# Generated by FakeRAM 2.0
VERSION 5.7 ;
BUSBITCHARS "[]" ;
PROPERTYDEFINITIONS
  MACRO width INTEGER ;
  MACRO depth INTEGER ;
  MACRO banks INTEGER ;
END PROPERTYDEFINITIONS
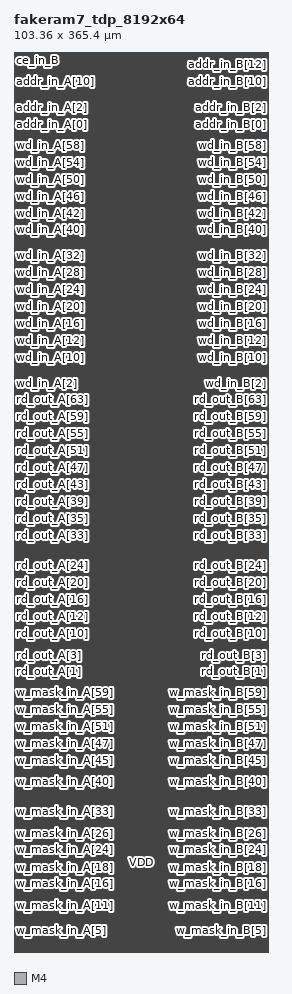
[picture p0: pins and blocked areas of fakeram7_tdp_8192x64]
MACRO fakeram7_tdp_8192x64
  PROPERTY width 64 ;
  PROPERTY depth 8192 ;
  PROPERTY banks 8 ;
  FOREIGN fakeram7_tdp_8192x64 0 0 ;
  SYMMETRY X Y ;
  SIZE 103.360 BY 365.400 ;
  CLASS BLOCK ;
  PIN w_mask_in_A[0]
    DIRECTION INPUT ;
    USE SIGNAL ;
    SHAPE ABUTMENT ;
    PORT
      LAYER M4 ;
      RECT 0.000 0.048 0.024 0.072 ;
    END
  END w_mask_in_A[0]
  PIN w_mask_in_B[0]
    DIRECTION INPUT ;
    USE SIGNAL ;
    SHAPE ABUTMENT ;
    PORT
      LAYER M4 ;
      RECT 103.336 0.048 103.360 0.072 ;
    END
  END w_mask_in_B[0]
  PIN w_mask_in_A[1]
    DIRECTION INPUT ;
    USE SIGNAL ;
    SHAPE ABUTMENT ;
    PORT
      LAYER M4 ;
      RECT 0.000 1.776 0.024 1.800 ;
    END
  END w_mask_in_A[1]
  PIN w_mask_in_B[1]
    DIRECTION INPUT ;
    USE SIGNAL ;
    SHAPE ABUTMENT ;
    PORT
      LAYER M4 ;
      RECT 103.336 1.776 103.360 1.800 ;
    END
  END w_mask_in_B[1]
  PIN w_mask_in_A[2]
    DIRECTION INPUT ;
    USE SIGNAL ;
    SHAPE ABUTMENT ;
    PORT
      LAYER M4 ;
      RECT 0.000 3.504 0.024 3.528 ;
    END
  END w_mask_in_A[2]
  PIN w_mask_in_B[2]
    DIRECTION INPUT ;
    USE SIGNAL ;
    SHAPE ABUTMENT ;
    PORT
      LAYER M4 ;
      RECT 103.336 3.504 103.360 3.528 ;
    END
  END w_mask_in_B[2]
  PIN w_mask_in_A[3]
    DIRECTION INPUT ;
    USE SIGNAL ;
    SHAPE ABUTMENT ;
    PORT
      LAYER M4 ;
      RECT 0.000 5.232 0.024 5.256 ;
    END
  END w_mask_in_A[3]
  PIN w_mask_in_B[3]
    DIRECTION INPUT ;
    USE SIGNAL ;
    SHAPE ABUTMENT ;
    PORT
      LAYER M4 ;
      RECT 103.336 5.232 103.360 5.256 ;
    END
  END w_mask_in_B[3]
  PIN w_mask_in_A[4]
    DIRECTION INPUT ;
    USE SIGNAL ;
    SHAPE ABUTMENT ;
    PORT
      LAYER M4 ;
      RECT 0.000 6.960 0.024 6.984 ;
    END
  END w_mask_in_A[4]
  PIN w_mask_in_B[4]
    DIRECTION INPUT ;
    USE SIGNAL ;
    SHAPE ABUTMENT ;
    PORT
      LAYER M4 ;
      RECT 103.336 6.960 103.360 6.984 ;
    END
  END w_mask_in_B[4]
  PIN w_mask_in_A[5]
    DIRECTION INPUT ;
    USE SIGNAL ;
    SHAPE ABUTMENT ;
    PORT
      LAYER M4 ;
      RECT 0.000 8.688 0.024 8.712 ;
    END
  END w_mask_in_A[5]
  PIN w_mask_in_B[5]
    DIRECTION INPUT ;
    USE SIGNAL ;
    SHAPE ABUTMENT ;
    PORT
      LAYER M4 ;
      RECT 103.336 8.688 103.360 8.712 ;
    END
  END w_mask_in_B[5]
  PIN w_mask_in_A[6]
    DIRECTION INPUT ;
    USE SIGNAL ;
    SHAPE ABUTMENT ;
    PORT
      LAYER M4 ;
      RECT 0.000 10.416 0.024 10.440 ;
    END
  END w_mask_in_A[6]
  PIN w_mask_in_B[6]
    DIRECTION INPUT ;
    USE SIGNAL ;
    SHAPE ABUTMENT ;
    PORT
      LAYER M4 ;
      RECT 103.336 10.416 103.360 10.440 ;
    END
  END w_mask_in_B[6]
  PIN w_mask_in_A[7]
    DIRECTION INPUT ;
    USE SIGNAL ;
    SHAPE ABUTMENT ;
    PORT
      LAYER M4 ;
      RECT 0.000 12.144 0.024 12.168 ;
    END
  END w_mask_in_A[7]
  PIN w_mask_in_B[7]
    DIRECTION INPUT ;
    USE SIGNAL ;
    SHAPE ABUTMENT ;
    PORT
      LAYER M4 ;
      RECT 103.336 12.144 103.360 12.168 ;
    END
  END w_mask_in_B[7]
  PIN w_mask_in_A[8]
    DIRECTION INPUT ;
    USE SIGNAL ;
    SHAPE ABUTMENT ;
    PORT
      LAYER M4 ;
      RECT 0.000 13.872 0.024 13.896 ;
    END
  END w_mask_in_A[8]
  PIN w_mask_in_B[8]
    DIRECTION INPUT ;
    USE SIGNAL ;
    SHAPE ABUTMENT ;
    PORT
      LAYER M4 ;
      RECT 103.336 13.872 103.360 13.896 ;
    END
  END w_mask_in_B[8]
  PIN w_mask_in_A[9]
    DIRECTION INPUT ;
    USE SIGNAL ;
    SHAPE ABUTMENT ;
    PORT
      LAYER M4 ;
      RECT 0.000 15.600 0.024 15.624 ;
    END
  END w_mask_in_A[9]
  PIN w_mask_in_B[9]
    DIRECTION INPUT ;
    USE SIGNAL ;
    SHAPE ABUTMENT ;
    PORT
      LAYER M4 ;
      RECT 103.336 15.600 103.360 15.624 ;
    END
  END w_mask_in_B[9]
  PIN w_mask_in_A[10]
    DIRECTION INPUT ;
    USE SIGNAL ;
    SHAPE ABUTMENT ;
    PORT
      LAYER M4 ;
      RECT 0.000 17.328 0.024 17.352 ;
    END
  END w_mask_in_A[10]
  PIN w_mask_in_B[10]
    DIRECTION INPUT ;
    USE SIGNAL ;
    SHAPE ABUTMENT ;
    PORT
      LAYER M4 ;
      RECT 103.336 17.328 103.360 17.352 ;
    END
  END w_mask_in_B[10]
  PIN w_mask_in_A[11]
    DIRECTION INPUT ;
    USE SIGNAL ;
    SHAPE ABUTMENT ;
    PORT
      LAYER M4 ;
      RECT 0.000 19.056 0.024 19.080 ;
    END
  END w_mask_in_A[11]
  PIN w_mask_in_B[11]
    DIRECTION INPUT ;
    USE SIGNAL ;
    SHAPE ABUTMENT ;
    PORT
      LAYER M4 ;
      RECT 103.336 19.056 103.360 19.080 ;
    END
  END w_mask_in_B[11]
  PIN w_mask_in_A[12]
    DIRECTION INPUT ;
    USE SIGNAL ;
    SHAPE ABUTMENT ;
    PORT
      LAYER M4 ;
      RECT 0.000 20.784 0.024 20.808 ;
    END
  END w_mask_in_A[12]
  PIN w_mask_in_B[12]
    DIRECTION INPUT ;
    USE SIGNAL ;
    SHAPE ABUTMENT ;
    PORT
      LAYER M4 ;
      RECT 103.336 20.784 103.360 20.808 ;
    END
  END w_mask_in_B[12]
  PIN w_mask_in_A[13]
    DIRECTION INPUT ;
    USE SIGNAL ;
    SHAPE ABUTMENT ;
    PORT
      LAYER M4 ;
      RECT 0.000 22.512 0.024 22.536 ;
    END
  END w_mask_in_A[13]
  PIN w_mask_in_B[13]
    DIRECTION INPUT ;
    USE SIGNAL ;
    SHAPE ABUTMENT ;
    PORT
      LAYER M4 ;
      RECT 103.336 22.512 103.360 22.536 ;
    END
  END w_mask_in_B[13]
  PIN w_mask_in_A[14]
    DIRECTION INPUT ;
    USE SIGNAL ;
    SHAPE ABUTMENT ;
    PORT
      LAYER M4 ;
      RECT 0.000 24.240 0.024 24.264 ;
    END
  END w_mask_in_A[14]
  PIN w_mask_in_B[14]
    DIRECTION INPUT ;
    USE SIGNAL ;
    SHAPE ABUTMENT ;
    PORT
      LAYER M4 ;
      RECT 103.336 24.240 103.360 24.264 ;
    END
  END w_mask_in_B[14]
  PIN w_mask_in_A[15]
    DIRECTION INPUT ;
    USE SIGNAL ;
    SHAPE ABUTMENT ;
    PORT
      LAYER M4 ;
      RECT 0.000 25.968 0.024 25.992 ;
    END
  END w_mask_in_A[15]
  PIN w_mask_in_B[15]
    DIRECTION INPUT ;
    USE SIGNAL ;
    SHAPE ABUTMENT ;
    PORT
      LAYER M4 ;
      RECT 103.336 25.968 103.360 25.992 ;
    END
  END w_mask_in_B[15]
  PIN w_mask_in_A[16]
    DIRECTION INPUT ;
    USE SIGNAL ;
    SHAPE ABUTMENT ;
    PORT
      LAYER M4 ;
      RECT 0.000 27.696 0.024 27.720 ;
    END
  END w_mask_in_A[16]
  PIN w_mask_in_B[16]
    DIRECTION INPUT ;
    USE SIGNAL ;
    SHAPE ABUTMENT ;
    PORT
      LAYER M4 ;
      RECT 103.336 27.696 103.360 27.720 ;
    END
  END w_mask_in_B[16]
  PIN w_mask_in_A[17]
    DIRECTION INPUT ;
    USE SIGNAL ;
    SHAPE ABUTMENT ;
    PORT
      LAYER M4 ;
      RECT 0.000 29.424 0.024 29.448 ;
    END
  END w_mask_in_A[17]
  PIN w_mask_in_B[17]
    DIRECTION INPUT ;
    USE SIGNAL ;
    SHAPE ABUTMENT ;
    PORT
      LAYER M4 ;
      RECT 103.336 29.424 103.360 29.448 ;
    END
  END w_mask_in_B[17]
  PIN w_mask_in_A[18]
    DIRECTION INPUT ;
    USE SIGNAL ;
    SHAPE ABUTMENT ;
    PORT
      LAYER M4 ;
      RECT 0.000 31.152 0.024 31.176 ;
    END
  END w_mask_in_A[18]
  PIN w_mask_in_B[18]
    DIRECTION INPUT ;
    USE SIGNAL ;
    SHAPE ABUTMENT ;
    PORT
      LAYER M4 ;
      RECT 103.336 31.152 103.360 31.176 ;
    END
  END w_mask_in_B[18]
  PIN w_mask_in_A[19]
    DIRECTION INPUT ;
    USE SIGNAL ;
    SHAPE ABUTMENT ;
    PORT
      LAYER M4 ;
      RECT 0.000 32.880 0.024 32.904 ;
    END
  END w_mask_in_A[19]
  PIN w_mask_in_B[19]
    DIRECTION INPUT ;
    USE SIGNAL ;
    SHAPE ABUTMENT ;
    PORT
      LAYER M4 ;
      RECT 103.336 32.880 103.360 32.904 ;
    END
  END w_mask_in_B[19]
  PIN w_mask_in_A[20]
    DIRECTION INPUT ;
    USE SIGNAL ;
    SHAPE ABUTMENT ;
    PORT
      LAYER M4 ;
      RECT 0.000 34.608 0.024 34.632 ;
    END
  END w_mask_in_A[20]
  PIN w_mask_in_B[20]
    DIRECTION INPUT ;
    USE SIGNAL ;
    SHAPE ABUTMENT ;
    PORT
      LAYER M4 ;
      RECT 103.336 34.608 103.360 34.632 ;
    END
  END w_mask_in_B[20]
  PIN w_mask_in_A[21]
    DIRECTION INPUT ;
    USE SIGNAL ;
    SHAPE ABUTMENT ;
    PORT
      LAYER M4 ;
      RECT 0.000 36.336 0.024 36.360 ;
    END
  END w_mask_in_A[21]
  PIN w_mask_in_B[21]
    DIRECTION INPUT ;
    USE SIGNAL ;
    SHAPE ABUTMENT ;
    PORT
      LAYER M4 ;
      RECT 103.336 36.336 103.360 36.360 ;
    END
  END w_mask_in_B[21]
  PIN w_mask_in_A[22]
    DIRECTION INPUT ;
    USE SIGNAL ;
    SHAPE ABUTMENT ;
    PORT
      LAYER M4 ;
      RECT 0.000 38.064 0.024 38.088 ;
    END
  END w_mask_in_A[22]
  PIN w_mask_in_B[22]
    DIRECTION INPUT ;
    USE SIGNAL ;
    SHAPE ABUTMENT ;
    PORT
      LAYER M4 ;
      RECT 103.336 38.064 103.360 38.088 ;
    END
  END w_mask_in_B[22]
  PIN w_mask_in_A[23]
    DIRECTION INPUT ;
    USE SIGNAL ;
    SHAPE ABUTMENT ;
    PORT
      LAYER M4 ;
      RECT 0.000 39.792 0.024 39.816 ;
    END
  END w_mask_in_A[23]
  PIN w_mask_in_B[23]
    DIRECTION INPUT ;
    USE SIGNAL ;
    SHAPE ABUTMENT ;
    PORT
      LAYER M4 ;
      RECT 103.336 39.792 103.360 39.816 ;
    END
  END w_mask_in_B[23]
  PIN w_mask_in_A[24]
    DIRECTION INPUT ;
    USE SIGNAL ;
    SHAPE ABUTMENT ;
    PORT
      LAYER M4 ;
      RECT 0.000 41.520 0.024 41.544 ;
    END
  END w_mask_in_A[24]
  PIN w_mask_in_B[24]
    DIRECTION INPUT ;
    USE SIGNAL ;
    SHAPE ABUTMENT ;
    PORT
      LAYER M4 ;
      RECT 103.336 41.520 103.360 41.544 ;
    END
  END w_mask_in_B[24]
  PIN w_mask_in_A[25]
    DIRECTION INPUT ;
    USE SIGNAL ;
    SHAPE ABUTMENT ;
    PORT
      LAYER M4 ;
      RECT 0.000 43.248 0.024 43.272 ;
    END
  END w_mask_in_A[25]
  PIN w_mask_in_B[25]
    DIRECTION INPUT ;
    USE SIGNAL ;
    SHAPE ABUTMENT ;
    PORT
      LAYER M4 ;
      RECT 103.336 43.248 103.360 43.272 ;
    END
  END w_mask_in_B[25]
  PIN w_mask_in_A[26]
    DIRECTION INPUT ;
    USE SIGNAL ;
    SHAPE ABUTMENT ;
    PORT
      LAYER M4 ;
      RECT 0.000 44.976 0.024 45.000 ;
    END
  END w_mask_in_A[26]
  PIN w_mask_in_B[26]
    DIRECTION INPUT ;
    USE SIGNAL ;
    SHAPE ABUTMENT ;
    PORT
      LAYER M4 ;
      RECT 103.336 44.976 103.360 45.000 ;
    END
  END w_mask_in_B[26]
  PIN w_mask_in_A[27]
    DIRECTION INPUT ;
    USE SIGNAL ;
    SHAPE ABUTMENT ;
    PORT
      LAYER M4 ;
      RECT 0.000 46.704 0.024 46.728 ;
    END
  END w_mask_in_A[27]
  PIN w_mask_in_B[27]
    DIRECTION INPUT ;
    USE SIGNAL ;
    SHAPE ABUTMENT ;
    PORT
      LAYER M4 ;
      RECT 103.336 46.704 103.360 46.728 ;
    END
  END w_mask_in_B[27]
  PIN w_mask_in_A[28]
    DIRECTION INPUT ;
    USE SIGNAL ;
    SHAPE ABUTMENT ;
    PORT
      LAYER M4 ;
      RECT 0.000 48.432 0.024 48.456 ;
    END
  END w_mask_in_A[28]
  PIN w_mask_in_B[28]
    DIRECTION INPUT ;
    USE SIGNAL ;
    SHAPE ABUTMENT ;
    PORT
      LAYER M4 ;
      RECT 103.336 48.432 103.360 48.456 ;
    END
  END w_mask_in_B[28]
  PIN w_mask_in_A[29]
    DIRECTION INPUT ;
    USE SIGNAL ;
    SHAPE ABUTMENT ;
    PORT
      LAYER M4 ;
      RECT 0.000 50.160 0.024 50.184 ;
    END
  END w_mask_in_A[29]
  PIN w_mask_in_B[29]
    DIRECTION INPUT ;
    USE SIGNAL ;
    SHAPE ABUTMENT ;
    PORT
      LAYER M4 ;
      RECT 103.336 50.160 103.360 50.184 ;
    END
  END w_mask_in_B[29]
  PIN w_mask_in_A[30]
    DIRECTION INPUT ;
    USE SIGNAL ;
    SHAPE ABUTMENT ;
    PORT
      LAYER M4 ;
      RECT 0.000 51.888 0.024 51.912 ;
    END
  END w_mask_in_A[30]
  PIN w_mask_in_B[30]
    DIRECTION INPUT ;
    USE SIGNAL ;
    SHAPE ABUTMENT ;
    PORT
      LAYER M4 ;
      RECT 103.336 51.888 103.360 51.912 ;
    END
  END w_mask_in_B[30]
  PIN w_mask_in_A[31]
    DIRECTION INPUT ;
    USE SIGNAL ;
    SHAPE ABUTMENT ;
    PORT
      LAYER M4 ;
      RECT 0.000 53.616 0.024 53.640 ;
    END
  END w_mask_in_A[31]
  PIN w_mask_in_B[31]
    DIRECTION INPUT ;
    USE SIGNAL ;
    SHAPE ABUTMENT ;
    PORT
      LAYER M4 ;
      RECT 103.336 53.616 103.360 53.640 ;
    END
  END w_mask_in_B[31]
  PIN w_mask_in_A[32]
    DIRECTION INPUT ;
    USE SIGNAL ;
    SHAPE ABUTMENT ;
    PORT
      LAYER M4 ;
      RECT 0.000 55.344 0.024 55.368 ;
    END
  END w_mask_in_A[32]
  PIN w_mask_in_B[32]
    DIRECTION INPUT ;
    USE SIGNAL ;
    SHAPE ABUTMENT ;
    PORT
      LAYER M4 ;
      RECT 103.336 55.344 103.360 55.368 ;
    END
  END w_mask_in_B[32]
  PIN w_mask_in_A[33]
    DIRECTION INPUT ;
    USE SIGNAL ;
    SHAPE ABUTMENT ;
    PORT
      LAYER M4 ;
      RECT 0.000 57.072 0.024 57.096 ;
    END
  END w_mask_in_A[33]
  PIN w_mask_in_B[33]
    DIRECTION INPUT ;
    USE SIGNAL ;
    SHAPE ABUTMENT ;
    PORT
      LAYER M4 ;
      RECT 103.336 57.072 103.360 57.096 ;
    END
  END w_mask_in_B[33]
  PIN w_mask_in_A[34]
    DIRECTION INPUT ;
    USE SIGNAL ;
    SHAPE ABUTMENT ;
    PORT
      LAYER M4 ;
      RECT 0.000 58.800 0.024 58.824 ;
    END
  END w_mask_in_A[34]
  PIN w_mask_in_B[34]
    DIRECTION INPUT ;
    USE SIGNAL ;
    SHAPE ABUTMENT ;
    PORT
      LAYER M4 ;
      RECT 103.336 58.800 103.360 58.824 ;
    END
  END w_mask_in_B[34]
  PIN w_mask_in_A[35]
    DIRECTION INPUT ;
    USE SIGNAL ;
    SHAPE ABUTMENT ;
    PORT
      LAYER M4 ;
      RECT 0.000 60.528 0.024 60.552 ;
    END
  END w_mask_in_A[35]
  PIN w_mask_in_B[35]
    DIRECTION INPUT ;
    USE SIGNAL ;
    SHAPE ABUTMENT ;
    PORT
      LAYER M4 ;
      RECT 103.336 60.528 103.360 60.552 ;
    END
  END w_mask_in_B[35]
  PIN w_mask_in_A[36]
    DIRECTION INPUT ;
    USE SIGNAL ;
    SHAPE ABUTMENT ;
    PORT
      LAYER M4 ;
      RECT 0.000 62.256 0.024 62.280 ;
    END
  END w_mask_in_A[36]
  PIN w_mask_in_B[36]
    DIRECTION INPUT ;
    USE SIGNAL ;
    SHAPE ABUTMENT ;
    PORT
      LAYER M4 ;
      RECT 103.336 62.256 103.360 62.280 ;
    END
  END w_mask_in_B[36]
  PIN w_mask_in_A[37]
    DIRECTION INPUT ;
    USE SIGNAL ;
    SHAPE ABUTMENT ;
    PORT
      LAYER M4 ;
      RECT 0.000 63.984 0.024 64.008 ;
    END
  END w_mask_in_A[37]
  PIN w_mask_in_B[37]
    DIRECTION INPUT ;
    USE SIGNAL ;
    SHAPE ABUTMENT ;
    PORT
      LAYER M4 ;
      RECT 103.336 63.984 103.360 64.008 ;
    END
  END w_mask_in_B[37]
  PIN w_mask_in_A[38]
    DIRECTION INPUT ;
    USE SIGNAL ;
    SHAPE ABUTMENT ;
    PORT
      LAYER M4 ;
      RECT 0.000 65.712 0.024 65.736 ;
    END
  END w_mask_in_A[38]
  PIN w_mask_in_B[38]
    DIRECTION INPUT ;
    USE SIGNAL ;
    SHAPE ABUTMENT ;
    PORT
      LAYER M4 ;
      RECT 103.336 65.712 103.360 65.736 ;
    END
  END w_mask_in_B[38]
  PIN w_mask_in_A[39]
    DIRECTION INPUT ;
    USE SIGNAL ;
    SHAPE ABUTMENT ;
    PORT
      LAYER M4 ;
      RECT 0.000 67.440 0.024 67.464 ;
    END
  END w_mask_in_A[39]
  PIN w_mask_in_B[39]
    DIRECTION INPUT ;
    USE SIGNAL ;
    SHAPE ABUTMENT ;
    PORT
      LAYER M4 ;
      RECT 103.336 67.440 103.360 67.464 ;
    END
  END w_mask_in_B[39]
  PIN w_mask_in_A[40]
    DIRECTION INPUT ;
    USE SIGNAL ;
    SHAPE ABUTMENT ;
    PORT
      LAYER M4 ;
      RECT 0.000 69.168 0.024 69.192 ;
    END
  END w_mask_in_A[40]
  PIN w_mask_in_B[40]
    DIRECTION INPUT ;
    USE SIGNAL ;
    SHAPE ABUTMENT ;
    PORT
      LAYER M4 ;
      RECT 103.336 69.168 103.360 69.192 ;
    END
  END w_mask_in_B[40]
  PIN w_mask_in_A[41]
    DIRECTION INPUT ;
    USE SIGNAL ;
    SHAPE ABUTMENT ;
    PORT
      LAYER M4 ;
      RECT 0.000 70.896 0.024 70.920 ;
    END
  END w_mask_in_A[41]
  PIN w_mask_in_B[41]
    DIRECTION INPUT ;
    USE SIGNAL ;
    SHAPE ABUTMENT ;
    PORT
      LAYER M4 ;
      RECT 103.336 70.896 103.360 70.920 ;
    END
  END w_mask_in_B[41]
  PIN w_mask_in_A[42]
    DIRECTION INPUT ;
    USE SIGNAL ;
    SHAPE ABUTMENT ;
    PORT
      LAYER M4 ;
      RECT 0.000 72.624 0.024 72.648 ;
    END
  END w_mask_in_A[42]
  PIN w_mask_in_B[42]
    DIRECTION INPUT ;
    USE SIGNAL ;
    SHAPE ABUTMENT ;
    PORT
      LAYER M4 ;
      RECT 103.336 72.624 103.360 72.648 ;
    END
  END w_mask_in_B[42]
  PIN w_mask_in_A[43]
    DIRECTION INPUT ;
    USE SIGNAL ;
    SHAPE ABUTMENT ;
    PORT
      LAYER M4 ;
      RECT 0.000 74.352 0.024 74.376 ;
    END
  END w_mask_in_A[43]
  PIN w_mask_in_B[43]
    DIRECTION INPUT ;
    USE SIGNAL ;
    SHAPE ABUTMENT ;
    PORT
      LAYER M4 ;
      RECT 103.336 74.352 103.360 74.376 ;
    END
  END w_mask_in_B[43]
  PIN w_mask_in_A[44]
    DIRECTION INPUT ;
    USE SIGNAL ;
    SHAPE ABUTMENT ;
    PORT
      LAYER M4 ;
      RECT 0.000 76.080 0.024 76.104 ;
    END
  END w_mask_in_A[44]
  PIN w_mask_in_B[44]
    DIRECTION INPUT ;
    USE SIGNAL ;
    SHAPE ABUTMENT ;
    PORT
      LAYER M4 ;
      RECT 103.336 76.080 103.360 76.104 ;
    END
  END w_mask_in_B[44]
  PIN w_mask_in_A[45]
    DIRECTION INPUT ;
    USE SIGNAL ;
    SHAPE ABUTMENT ;
    PORT
      LAYER M4 ;
      RECT 0.000 77.808 0.024 77.832 ;
    END
  END w_mask_in_A[45]
  PIN w_mask_in_B[45]
    DIRECTION INPUT ;
    USE SIGNAL ;
    SHAPE ABUTMENT ;
    PORT
      LAYER M4 ;
      RECT 103.336 77.808 103.360 77.832 ;
    END
  END w_mask_in_B[45]
  PIN w_mask_in_A[46]
    DIRECTION INPUT ;
    USE SIGNAL ;
    SHAPE ABUTMENT ;
    PORT
      LAYER M4 ;
      RECT 0.000 79.536 0.024 79.560 ;
    END
  END w_mask_in_A[46]
  PIN w_mask_in_B[46]
    DIRECTION INPUT ;
    USE SIGNAL ;
    SHAPE ABUTMENT ;
    PORT
      LAYER M4 ;
      RECT 103.336 79.536 103.360 79.560 ;
    END
  END w_mask_in_B[46]
  PIN w_mask_in_A[47]
    DIRECTION INPUT ;
    USE SIGNAL ;
    SHAPE ABUTMENT ;
    PORT
      LAYER M4 ;
      RECT 0.000 81.264 0.024 81.288 ;
    END
  END w_mask_in_A[47]
  PIN w_mask_in_B[47]
    DIRECTION INPUT ;
    USE SIGNAL ;
    SHAPE ABUTMENT ;
    PORT
      LAYER M4 ;
      RECT 103.336 81.264 103.360 81.288 ;
    END
  END w_mask_in_B[47]
  PIN w_mask_in_A[48]
    DIRECTION INPUT ;
    USE SIGNAL ;
    SHAPE ABUTMENT ;
    PORT
      LAYER M4 ;
      RECT 0.000 82.992 0.024 83.016 ;
    END
  END w_mask_in_A[48]
  PIN w_mask_in_B[48]
    DIRECTION INPUT ;
    USE SIGNAL ;
    SHAPE ABUTMENT ;
    PORT
      LAYER M4 ;
      RECT 103.336 82.992 103.360 83.016 ;
    END
  END w_mask_in_B[48]
  PIN w_mask_in_A[49]
    DIRECTION INPUT ;
    USE SIGNAL ;
    SHAPE ABUTMENT ;
    PORT
      LAYER M4 ;
      RECT 0.000 84.720 0.024 84.744 ;
    END
  END w_mask_in_A[49]
  PIN w_mask_in_B[49]
    DIRECTION INPUT ;
    USE SIGNAL ;
    SHAPE ABUTMENT ;
    PORT
      LAYER M4 ;
      RECT 103.336 84.720 103.360 84.744 ;
    END
  END w_mask_in_B[49]
  PIN w_mask_in_A[50]
    DIRECTION INPUT ;
    USE SIGNAL ;
    SHAPE ABUTMENT ;
    PORT
      LAYER M4 ;
      RECT 0.000 86.448 0.024 86.472 ;
    END
  END w_mask_in_A[50]
  PIN w_mask_in_B[50]
    DIRECTION INPUT ;
    USE SIGNAL ;
    SHAPE ABUTMENT ;
    PORT
      LAYER M4 ;
      RECT 103.336 86.448 103.360 86.472 ;
    END
  END w_mask_in_B[50]
  PIN w_mask_in_A[51]
    DIRECTION INPUT ;
    USE SIGNAL ;
    SHAPE ABUTMENT ;
    PORT
      LAYER M4 ;
      RECT 0.000 88.176 0.024 88.200 ;
    END
  END w_mask_in_A[51]
  PIN w_mask_in_B[51]
    DIRECTION INPUT ;
    USE SIGNAL ;
    SHAPE ABUTMENT ;
    PORT
      LAYER M4 ;
      RECT 103.336 88.176 103.360 88.200 ;
    END
  END w_mask_in_B[51]
  PIN w_mask_in_A[52]
    DIRECTION INPUT ;
    USE SIGNAL ;
    SHAPE ABUTMENT ;
    PORT
      LAYER M4 ;
      RECT 0.000 89.904 0.024 89.928 ;
    END
  END w_mask_in_A[52]
  PIN w_mask_in_B[52]
    DIRECTION INPUT ;
    USE SIGNAL ;
    SHAPE ABUTMENT ;
    PORT
      LAYER M4 ;
      RECT 103.336 89.904 103.360 89.928 ;
    END
  END w_mask_in_B[52]
  PIN w_mask_in_A[53]
    DIRECTION INPUT ;
    USE SIGNAL ;
    SHAPE ABUTMENT ;
    PORT
      LAYER M4 ;
      RECT 0.000 91.632 0.024 91.656 ;
    END
  END w_mask_in_A[53]
  PIN w_mask_in_B[53]
    DIRECTION INPUT ;
    USE SIGNAL ;
    SHAPE ABUTMENT ;
    PORT
      LAYER M4 ;
      RECT 103.336 91.632 103.360 91.656 ;
    END
  END w_mask_in_B[53]
  PIN w_mask_in_A[54]
    DIRECTION INPUT ;
    USE SIGNAL ;
    SHAPE ABUTMENT ;
    PORT
      LAYER M4 ;
      RECT 0.000 93.360 0.024 93.384 ;
    END
  END w_mask_in_A[54]
  PIN w_mask_in_B[54]
    DIRECTION INPUT ;
    USE SIGNAL ;
    SHAPE ABUTMENT ;
    PORT
      LAYER M4 ;
      RECT 103.336 93.360 103.360 93.384 ;
    END
  END w_mask_in_B[54]
  PIN w_mask_in_A[55]
    DIRECTION INPUT ;
    USE SIGNAL ;
    SHAPE ABUTMENT ;
    PORT
      LAYER M4 ;
      RECT 0.000 95.088 0.024 95.112 ;
    END
  END w_mask_in_A[55]
  PIN w_mask_in_B[55]
    DIRECTION INPUT ;
    USE SIGNAL ;
    SHAPE ABUTMENT ;
    PORT
      LAYER M4 ;
      RECT 103.336 95.088 103.360 95.112 ;
    END
  END w_mask_in_B[55]
  PIN w_mask_in_A[56]
    DIRECTION INPUT ;
    USE SIGNAL ;
    SHAPE ABUTMENT ;
    PORT
      LAYER M4 ;
      RECT 0.000 96.816 0.024 96.840 ;
    END
  END w_mask_in_A[56]
  PIN w_mask_in_B[56]
    DIRECTION INPUT ;
    USE SIGNAL ;
    SHAPE ABUTMENT ;
    PORT
      LAYER M4 ;
      RECT 103.336 96.816 103.360 96.840 ;
    END
  END w_mask_in_B[56]
  PIN w_mask_in_A[57]
    DIRECTION INPUT ;
    USE SIGNAL ;
    SHAPE ABUTMENT ;
    PORT
      LAYER M4 ;
      RECT 0.000 98.544 0.024 98.568 ;
    END
  END w_mask_in_A[57]
  PIN w_mask_in_B[57]
    DIRECTION INPUT ;
    USE SIGNAL ;
    SHAPE ABUTMENT ;
    PORT
      LAYER M4 ;
      RECT 103.336 98.544 103.360 98.568 ;
    END
  END w_mask_in_B[57]
  PIN w_mask_in_A[58]
    DIRECTION INPUT ;
    USE SIGNAL ;
    SHAPE ABUTMENT ;
    PORT
      LAYER M4 ;
      RECT 0.000 100.272 0.024 100.296 ;
    END
  END w_mask_in_A[58]
  PIN w_mask_in_B[58]
    DIRECTION INPUT ;
    USE SIGNAL ;
    SHAPE ABUTMENT ;
    PORT
      LAYER M4 ;
      RECT 103.336 100.272 103.360 100.296 ;
    END
  END w_mask_in_B[58]
  PIN w_mask_in_A[59]
    DIRECTION INPUT ;
    USE SIGNAL ;
    SHAPE ABUTMENT ;
    PORT
      LAYER M4 ;
      RECT 0.000 102.000 0.024 102.024 ;
    END
  END w_mask_in_A[59]
  PIN w_mask_in_B[59]
    DIRECTION INPUT ;
    USE SIGNAL ;
    SHAPE ABUTMENT ;
    PORT
      LAYER M4 ;
      RECT 103.336 102.000 103.360 102.024 ;
    END
  END w_mask_in_B[59]
  PIN w_mask_in_A[60]
    DIRECTION INPUT ;
    USE SIGNAL ;
    SHAPE ABUTMENT ;
    PORT
      LAYER M4 ;
      RECT 0.000 103.728 0.024 103.752 ;
    END
  END w_mask_in_A[60]
  PIN w_mask_in_B[60]
    DIRECTION INPUT ;
    USE SIGNAL ;
    SHAPE ABUTMENT ;
    PORT
      LAYER M4 ;
      RECT 103.336 103.728 103.360 103.752 ;
    END
  END w_mask_in_B[60]
  PIN w_mask_in_A[61]
    DIRECTION INPUT ;
    USE SIGNAL ;
    SHAPE ABUTMENT ;
    PORT
      LAYER M4 ;
      RECT 0.000 105.456 0.024 105.480 ;
    END
  END w_mask_in_A[61]
  PIN w_mask_in_B[61]
    DIRECTION INPUT ;
    USE SIGNAL ;
    SHAPE ABUTMENT ;
    PORT
      LAYER M4 ;
      RECT 103.336 105.456 103.360 105.480 ;
    END
  END w_mask_in_B[61]
  PIN w_mask_in_A[62]
    DIRECTION INPUT ;
    USE SIGNAL ;
    SHAPE ABUTMENT ;
    PORT
      LAYER M4 ;
      RECT 0.000 107.184 0.024 107.208 ;
    END
  END w_mask_in_A[62]
  PIN w_mask_in_B[62]
    DIRECTION INPUT ;
    USE SIGNAL ;
    SHAPE ABUTMENT ;
    PORT
      LAYER M4 ;
      RECT 103.336 107.184 103.360 107.208 ;
    END
  END w_mask_in_B[62]
  PIN w_mask_in_A[63]
    DIRECTION INPUT ;
    USE SIGNAL ;
    SHAPE ABUTMENT ;
    PORT
      LAYER M4 ;
      RECT 0.000 108.912 0.024 108.936 ;
    END
  END w_mask_in_A[63]
  PIN w_mask_in_B[63]
    DIRECTION INPUT ;
    USE SIGNAL ;
    SHAPE ABUTMENT ;
    PORT
      LAYER M4 ;
      RECT 103.336 108.912 103.360 108.936 ;
    END
  END w_mask_in_B[63]
  PIN rd_out_A[0]
    DIRECTION OUTPUT ;
    USE SIGNAL ;
    SHAPE ABUTMENT ;
    PORT
      LAYER M4 ;
      RECT 0.000 112.080 0.024 112.104 ;
    END
  END rd_out_A[0]
  PIN rd_out_B[0]
    DIRECTION OUTPUT ;
    USE SIGNAL ;
    SHAPE ABUTMENT ;
    PORT
      LAYER M4 ;
      RECT 103.336 112.080 103.360 112.104 ;
    END
  END rd_out_B[0]
  PIN rd_out_A[1]
    DIRECTION OUTPUT ;
    USE SIGNAL ;
    SHAPE ABUTMENT ;
    PORT
      LAYER M4 ;
      RECT 0.000 113.808 0.024 113.832 ;
    END
  END rd_out_A[1]
  PIN rd_out_B[1]
    DIRECTION OUTPUT ;
    USE SIGNAL ;
    SHAPE ABUTMENT ;
    PORT
      LAYER M4 ;
      RECT 103.336 113.808 103.360 113.832 ;
    END
  END rd_out_B[1]
  PIN rd_out_A[2]
    DIRECTION OUTPUT ;
    USE SIGNAL ;
    SHAPE ABUTMENT ;
    PORT
      LAYER M4 ;
      RECT 0.000 115.536 0.024 115.560 ;
    END
  END rd_out_A[2]
  PIN rd_out_B[2]
    DIRECTION OUTPUT ;
    USE SIGNAL ;
    SHAPE ABUTMENT ;
    PORT
      LAYER M4 ;
      RECT 103.336 115.536 103.360 115.560 ;
    END
  END rd_out_B[2]
  PIN rd_out_A[3]
    DIRECTION OUTPUT ;
    USE SIGNAL ;
    SHAPE ABUTMENT ;
    PORT
      LAYER M4 ;
      RECT 0.000 117.264 0.024 117.288 ;
    END
  END rd_out_A[3]
  PIN rd_out_B[3]
    DIRECTION OUTPUT ;
    USE SIGNAL ;
    SHAPE ABUTMENT ;
    PORT
      LAYER M4 ;
      RECT 103.336 117.264 103.360 117.288 ;
    END
  END rd_out_B[3]
  PIN rd_out_A[4]
    DIRECTION OUTPUT ;
    USE SIGNAL ;
    SHAPE ABUTMENT ;
    PORT
      LAYER M4 ;
      RECT 0.000 118.992 0.024 119.016 ;
    END
  END rd_out_A[4]
  PIN rd_out_B[4]
    DIRECTION OUTPUT ;
    USE SIGNAL ;
    SHAPE ABUTMENT ;
    PORT
      LAYER M4 ;
      RECT 103.336 118.992 103.360 119.016 ;
    END
  END rd_out_B[4]
  PIN rd_out_A[5]
    DIRECTION OUTPUT ;
    USE SIGNAL ;
    SHAPE ABUTMENT ;
    PORT
      LAYER M4 ;
      RECT 0.000 120.720 0.024 120.744 ;
    END
  END rd_out_A[5]
  PIN rd_out_B[5]
    DIRECTION OUTPUT ;
    USE SIGNAL ;
    SHAPE ABUTMENT ;
    PORT
      LAYER M4 ;
      RECT 103.336 120.720 103.360 120.744 ;
    END
  END rd_out_B[5]
  PIN rd_out_A[6]
    DIRECTION OUTPUT ;
    USE SIGNAL ;
    SHAPE ABUTMENT ;
    PORT
      LAYER M4 ;
      RECT 0.000 122.448 0.024 122.472 ;
    END
  END rd_out_A[6]
  PIN rd_out_B[6]
    DIRECTION OUTPUT ;
    USE SIGNAL ;
    SHAPE ABUTMENT ;
    PORT
      LAYER M4 ;
      RECT 103.336 122.448 103.360 122.472 ;
    END
  END rd_out_B[6]
  PIN rd_out_A[7]
    DIRECTION OUTPUT ;
    USE SIGNAL ;
    SHAPE ABUTMENT ;
    PORT
      LAYER M4 ;
      RECT 0.000 124.176 0.024 124.200 ;
    END
  END rd_out_A[7]
  PIN rd_out_B[7]
    DIRECTION OUTPUT ;
    USE SIGNAL ;
    SHAPE ABUTMENT ;
    PORT
      LAYER M4 ;
      RECT 103.336 124.176 103.360 124.200 ;
    END
  END rd_out_B[7]
  PIN rd_out_A[8]
    DIRECTION OUTPUT ;
    USE SIGNAL ;
    SHAPE ABUTMENT ;
    PORT
      LAYER M4 ;
      RECT 0.000 125.904 0.024 125.928 ;
    END
  END rd_out_A[8]
  PIN rd_out_B[8]
    DIRECTION OUTPUT ;
    USE SIGNAL ;
    SHAPE ABUTMENT ;
    PORT
      LAYER M4 ;
      RECT 103.336 125.904 103.360 125.928 ;
    END
  END rd_out_B[8]
  PIN rd_out_A[9]
    DIRECTION OUTPUT ;
    USE SIGNAL ;
    SHAPE ABUTMENT ;
    PORT
      LAYER M4 ;
      RECT 0.000 127.632 0.024 127.656 ;
    END
  END rd_out_A[9]
  PIN rd_out_B[9]
    DIRECTION OUTPUT ;
    USE SIGNAL ;
    SHAPE ABUTMENT ;
    PORT
      LAYER M4 ;
      RECT 103.336 127.632 103.360 127.656 ;
    END
  END rd_out_B[9]
  PIN rd_out_A[10]
    DIRECTION OUTPUT ;
    USE SIGNAL ;
    SHAPE ABUTMENT ;
    PORT
      LAYER M4 ;
      RECT 0.000 129.360 0.024 129.384 ;
    END
  END rd_out_A[10]
  PIN rd_out_B[10]
    DIRECTION OUTPUT ;
    USE SIGNAL ;
    SHAPE ABUTMENT ;
    PORT
      LAYER M4 ;
      RECT 103.336 129.360 103.360 129.384 ;
    END
  END rd_out_B[10]
  PIN rd_out_A[11]
    DIRECTION OUTPUT ;
    USE SIGNAL ;
    SHAPE ABUTMENT ;
    PORT
      LAYER M4 ;
      RECT 0.000 131.088 0.024 131.112 ;
    END
  END rd_out_A[11]
  PIN rd_out_B[11]
    DIRECTION OUTPUT ;
    USE SIGNAL ;
    SHAPE ABUTMENT ;
    PORT
      LAYER M4 ;
      RECT 103.336 131.088 103.360 131.112 ;
    END
  END rd_out_B[11]
  PIN rd_out_A[12]
    DIRECTION OUTPUT ;
    USE SIGNAL ;
    SHAPE ABUTMENT ;
    PORT
      LAYER M4 ;
      RECT 0.000 132.816 0.024 132.840 ;
    END
  END rd_out_A[12]
  PIN rd_out_B[12]
    DIRECTION OUTPUT ;
    USE SIGNAL ;
    SHAPE ABUTMENT ;
    PORT
      LAYER M4 ;
      RECT 103.336 132.816 103.360 132.840 ;
    END
  END rd_out_B[12]
  PIN rd_out_A[13]
    DIRECTION OUTPUT ;
    USE SIGNAL ;
    SHAPE ABUTMENT ;
    PORT
      LAYER M4 ;
      RECT 0.000 134.544 0.024 134.568 ;
    END
  END rd_out_A[13]
  PIN rd_out_B[13]
    DIRECTION OUTPUT ;
    USE SIGNAL ;
    SHAPE ABUTMENT ;
    PORT
      LAYER M4 ;
      RECT 103.336 134.544 103.360 134.568 ;
    END
  END rd_out_B[13]
  PIN rd_out_A[14]
    DIRECTION OUTPUT ;
    USE SIGNAL ;
    SHAPE ABUTMENT ;
    PORT
      LAYER M4 ;
      RECT 0.000 136.272 0.024 136.296 ;
    END
  END rd_out_A[14]
  PIN rd_out_B[14]
    DIRECTION OUTPUT ;
    USE SIGNAL ;
    SHAPE ABUTMENT ;
    PORT
      LAYER M4 ;
      RECT 103.336 136.272 103.360 136.296 ;
    END
  END rd_out_B[14]
  PIN rd_out_A[15]
    DIRECTION OUTPUT ;
    USE SIGNAL ;
    SHAPE ABUTMENT ;
    PORT
      LAYER M4 ;
      RECT 0.000 138.000 0.024 138.024 ;
    END
  END rd_out_A[15]
  PIN rd_out_B[15]
    DIRECTION OUTPUT ;
    USE SIGNAL ;
    SHAPE ABUTMENT ;
    PORT
      LAYER M4 ;
      RECT 103.336 138.000 103.360 138.024 ;
    END
  END rd_out_B[15]
  PIN rd_out_A[16]
    DIRECTION OUTPUT ;
    USE SIGNAL ;
    SHAPE ABUTMENT ;
    PORT
      LAYER M4 ;
      RECT 0.000 139.728 0.024 139.752 ;
    END
  END rd_out_A[16]
  PIN rd_out_B[16]
    DIRECTION OUTPUT ;
    USE SIGNAL ;
    SHAPE ABUTMENT ;
    PORT
      LAYER M4 ;
      RECT 103.336 139.728 103.360 139.752 ;
    END
  END rd_out_B[16]
  PIN rd_out_A[17]
    DIRECTION OUTPUT ;
    USE SIGNAL ;
    SHAPE ABUTMENT ;
    PORT
      LAYER M4 ;
      RECT 0.000 141.456 0.024 141.480 ;
    END
  END rd_out_A[17]
  PIN rd_out_B[17]
    DIRECTION OUTPUT ;
    USE SIGNAL ;
    SHAPE ABUTMENT ;
    PORT
      LAYER M4 ;
      RECT 103.336 141.456 103.360 141.480 ;
    END
  END rd_out_B[17]
  PIN rd_out_A[18]
    DIRECTION OUTPUT ;
    USE SIGNAL ;
    SHAPE ABUTMENT ;
    PORT
      LAYER M4 ;
      RECT 0.000 143.184 0.024 143.208 ;
    END
  END rd_out_A[18]
  PIN rd_out_B[18]
    DIRECTION OUTPUT ;
    USE SIGNAL ;
    SHAPE ABUTMENT ;
    PORT
      LAYER M4 ;
      RECT 103.336 143.184 103.360 143.208 ;
    END
  END rd_out_B[18]
  PIN rd_out_A[19]
    DIRECTION OUTPUT ;
    USE SIGNAL ;
    SHAPE ABUTMENT ;
    PORT
      LAYER M4 ;
      RECT 0.000 144.912 0.024 144.936 ;
    END
  END rd_out_A[19]
  PIN rd_out_B[19]
    DIRECTION OUTPUT ;
    USE SIGNAL ;
    SHAPE ABUTMENT ;
    PORT
      LAYER M4 ;
      RECT 103.336 144.912 103.360 144.936 ;
    END
  END rd_out_B[19]
  PIN rd_out_A[20]
    DIRECTION OUTPUT ;
    USE SIGNAL ;
    SHAPE ABUTMENT ;
    PORT
      LAYER M4 ;
      RECT 0.000 146.640 0.024 146.664 ;
    END
  END rd_out_A[20]
  PIN rd_out_B[20]
    DIRECTION OUTPUT ;
    USE SIGNAL ;
    SHAPE ABUTMENT ;
    PORT
      LAYER M4 ;
      RECT 103.336 146.640 103.360 146.664 ;
    END
  END rd_out_B[20]
  PIN rd_out_A[21]
    DIRECTION OUTPUT ;
    USE SIGNAL ;
    SHAPE ABUTMENT ;
    PORT
      LAYER M4 ;
      RECT 0.000 148.368 0.024 148.392 ;
    END
  END rd_out_A[21]
  PIN rd_out_B[21]
    DIRECTION OUTPUT ;
    USE SIGNAL ;
    SHAPE ABUTMENT ;
    PORT
      LAYER M4 ;
      RECT 103.336 148.368 103.360 148.392 ;
    END
  END rd_out_B[21]
  PIN rd_out_A[22]
    DIRECTION OUTPUT ;
    USE SIGNAL ;
    SHAPE ABUTMENT ;
    PORT
      LAYER M4 ;
      RECT 0.000 150.096 0.024 150.120 ;
    END
  END rd_out_A[22]
  PIN rd_out_B[22]
    DIRECTION OUTPUT ;
    USE SIGNAL ;
    SHAPE ABUTMENT ;
    PORT
      LAYER M4 ;
      RECT 103.336 150.096 103.360 150.120 ;
    END
  END rd_out_B[22]
  PIN rd_out_A[23]
    DIRECTION OUTPUT ;
    USE SIGNAL ;
    SHAPE ABUTMENT ;
    PORT
      LAYER M4 ;
      RECT 0.000 151.824 0.024 151.848 ;
    END
  END rd_out_A[23]
  PIN rd_out_B[23]
    DIRECTION OUTPUT ;
    USE SIGNAL ;
    SHAPE ABUTMENT ;
    PORT
      LAYER M4 ;
      RECT 103.336 151.824 103.360 151.848 ;
    END
  END rd_out_B[23]
  PIN rd_out_A[24]
    DIRECTION OUTPUT ;
    USE SIGNAL ;
    SHAPE ABUTMENT ;
    PORT
      LAYER M4 ;
      RECT 0.000 153.552 0.024 153.576 ;
    END
  END rd_out_A[24]
  PIN rd_out_B[24]
    DIRECTION OUTPUT ;
    USE SIGNAL ;
    SHAPE ABUTMENT ;
    PORT
      LAYER M4 ;
      RECT 103.336 153.552 103.360 153.576 ;
    END
  END rd_out_B[24]
  PIN rd_out_A[25]
    DIRECTION OUTPUT ;
    USE SIGNAL ;
    SHAPE ABUTMENT ;
    PORT
      LAYER M4 ;
      RECT 0.000 155.280 0.024 155.304 ;
    END
  END rd_out_A[25]
  PIN rd_out_B[25]
    DIRECTION OUTPUT ;
    USE SIGNAL ;
    SHAPE ABUTMENT ;
    PORT
      LAYER M4 ;
      RECT 103.336 155.280 103.360 155.304 ;
    END
  END rd_out_B[25]
  PIN rd_out_A[26]
    DIRECTION OUTPUT ;
    USE SIGNAL ;
    SHAPE ABUTMENT ;
    PORT
      LAYER M4 ;
      RECT 0.000 157.008 0.024 157.032 ;
    END
  END rd_out_A[26]
  PIN rd_out_B[26]
    DIRECTION OUTPUT ;
    USE SIGNAL ;
    SHAPE ABUTMENT ;
    PORT
      LAYER M4 ;
      RECT 103.336 157.008 103.360 157.032 ;
    END
  END rd_out_B[26]
  PIN rd_out_A[27]
    DIRECTION OUTPUT ;
    USE SIGNAL ;
    SHAPE ABUTMENT ;
    PORT
      LAYER M4 ;
      RECT 0.000 158.736 0.024 158.760 ;
    END
  END rd_out_A[27]
  PIN rd_out_B[27]
    DIRECTION OUTPUT ;
    USE SIGNAL ;
    SHAPE ABUTMENT ;
    PORT
      LAYER M4 ;
      RECT 103.336 158.736 103.360 158.760 ;
    END
  END rd_out_B[27]
  PIN rd_out_A[28]
    DIRECTION OUTPUT ;
    USE SIGNAL ;
    SHAPE ABUTMENT ;
    PORT
      LAYER M4 ;
      RECT 0.000 160.464 0.024 160.488 ;
    END
  END rd_out_A[28]
  PIN rd_out_B[28]
    DIRECTION OUTPUT ;
    USE SIGNAL ;
    SHAPE ABUTMENT ;
    PORT
      LAYER M4 ;
      RECT 103.336 160.464 103.360 160.488 ;
    END
  END rd_out_B[28]
  PIN rd_out_A[29]
    DIRECTION OUTPUT ;
    USE SIGNAL ;
    SHAPE ABUTMENT ;
    PORT
      LAYER M4 ;
      RECT 0.000 162.192 0.024 162.216 ;
    END
  END rd_out_A[29]
  PIN rd_out_B[29]
    DIRECTION OUTPUT ;
    USE SIGNAL ;
    SHAPE ABUTMENT ;
    PORT
      LAYER M4 ;
      RECT 103.336 162.192 103.360 162.216 ;
    END
  END rd_out_B[29]
  PIN rd_out_A[30]
    DIRECTION OUTPUT ;
    USE SIGNAL ;
    SHAPE ABUTMENT ;
    PORT
      LAYER M4 ;
      RECT 0.000 163.920 0.024 163.944 ;
    END
  END rd_out_A[30]
  PIN rd_out_B[30]
    DIRECTION OUTPUT ;
    USE SIGNAL ;
    SHAPE ABUTMENT ;
    PORT
      LAYER M4 ;
      RECT 103.336 163.920 103.360 163.944 ;
    END
  END rd_out_B[30]
  PIN rd_out_A[31]
    DIRECTION OUTPUT ;
    USE SIGNAL ;
    SHAPE ABUTMENT ;
    PORT
      LAYER M4 ;
      RECT 0.000 165.648 0.024 165.672 ;
    END
  END rd_out_A[31]
  PIN rd_out_B[31]
    DIRECTION OUTPUT ;
    USE SIGNAL ;
    SHAPE ABUTMENT ;
    PORT
      LAYER M4 ;
      RECT 103.336 165.648 103.360 165.672 ;
    END
  END rd_out_B[31]
  PIN rd_out_A[32]
    DIRECTION OUTPUT ;
    USE SIGNAL ;
    SHAPE ABUTMENT ;
    PORT
      LAYER M4 ;
      RECT 0.000 167.376 0.024 167.400 ;
    END
  END rd_out_A[32]
  PIN rd_out_B[32]
    DIRECTION OUTPUT ;
    USE SIGNAL ;
    SHAPE ABUTMENT ;
    PORT
      LAYER M4 ;
      RECT 103.336 167.376 103.360 167.400 ;
    END
  END rd_out_B[32]
  PIN rd_out_A[33]
    DIRECTION OUTPUT ;
    USE SIGNAL ;
    SHAPE ABUTMENT ;
    PORT
      LAYER M4 ;
      RECT 0.000 169.104 0.024 169.128 ;
    END
  END rd_out_A[33]
  PIN rd_out_B[33]
    DIRECTION OUTPUT ;
    USE SIGNAL ;
    SHAPE ABUTMENT ;
    PORT
      LAYER M4 ;
      RECT 103.336 169.104 103.360 169.128 ;
    END
  END rd_out_B[33]
  PIN rd_out_A[34]
    DIRECTION OUTPUT ;
    USE SIGNAL ;
    SHAPE ABUTMENT ;
    PORT
      LAYER M4 ;
      RECT 0.000 170.832 0.024 170.856 ;
    END
  END rd_out_A[34]
  PIN rd_out_B[34]
    DIRECTION OUTPUT ;
    USE SIGNAL ;
    SHAPE ABUTMENT ;
    PORT
      LAYER M4 ;
      RECT 103.336 170.832 103.360 170.856 ;
    END
  END rd_out_B[34]
  PIN rd_out_A[35]
    DIRECTION OUTPUT ;
    USE SIGNAL ;
    SHAPE ABUTMENT ;
    PORT
      LAYER M4 ;
      RECT 0.000 172.560 0.024 172.584 ;
    END
  END rd_out_A[35]
  PIN rd_out_B[35]
    DIRECTION OUTPUT ;
    USE SIGNAL ;
    SHAPE ABUTMENT ;
    PORT
      LAYER M4 ;
      RECT 103.336 172.560 103.360 172.584 ;
    END
  END rd_out_B[35]
  PIN rd_out_A[36]
    DIRECTION OUTPUT ;
    USE SIGNAL ;
    SHAPE ABUTMENT ;
    PORT
      LAYER M4 ;
      RECT 0.000 174.288 0.024 174.312 ;
    END
  END rd_out_A[36]
  PIN rd_out_B[36]
    DIRECTION OUTPUT ;
    USE SIGNAL ;
    SHAPE ABUTMENT ;
    PORT
      LAYER M4 ;
      RECT 103.336 174.288 103.360 174.312 ;
    END
  END rd_out_B[36]
  PIN rd_out_A[37]
    DIRECTION OUTPUT ;
    USE SIGNAL ;
    SHAPE ABUTMENT ;
    PORT
      LAYER M4 ;
      RECT 0.000 176.016 0.024 176.040 ;
    END
  END rd_out_A[37]
  PIN rd_out_B[37]
    DIRECTION OUTPUT ;
    USE SIGNAL ;
    SHAPE ABUTMENT ;
    PORT
      LAYER M4 ;
      RECT 103.336 176.016 103.360 176.040 ;
    END
  END rd_out_B[37]
  PIN rd_out_A[38]
    DIRECTION OUTPUT ;
    USE SIGNAL ;
    SHAPE ABUTMENT ;
    PORT
      LAYER M4 ;
      RECT 0.000 177.744 0.024 177.768 ;
    END
  END rd_out_A[38]
  PIN rd_out_B[38]
    DIRECTION OUTPUT ;
    USE SIGNAL ;
    SHAPE ABUTMENT ;
    PORT
      LAYER M4 ;
      RECT 103.336 177.744 103.360 177.768 ;
    END
  END rd_out_B[38]
  PIN rd_out_A[39]
    DIRECTION OUTPUT ;
    USE SIGNAL ;
    SHAPE ABUTMENT ;
    PORT
      LAYER M4 ;
      RECT 0.000 179.472 0.024 179.496 ;
    END
  END rd_out_A[39]
  PIN rd_out_B[39]
    DIRECTION OUTPUT ;
    USE SIGNAL ;
    SHAPE ABUTMENT ;
    PORT
      LAYER M4 ;
      RECT 103.336 179.472 103.360 179.496 ;
    END
  END rd_out_B[39]
  PIN rd_out_A[40]
    DIRECTION OUTPUT ;
    USE SIGNAL ;
    SHAPE ABUTMENT ;
    PORT
      LAYER M4 ;
      RECT 0.000 181.200 0.024 181.224 ;
    END
  END rd_out_A[40]
  PIN rd_out_B[40]
    DIRECTION OUTPUT ;
    USE SIGNAL ;
    SHAPE ABUTMENT ;
    PORT
      LAYER M4 ;
      RECT 103.336 181.200 103.360 181.224 ;
    END
  END rd_out_B[40]
  PIN rd_out_A[41]
    DIRECTION OUTPUT ;
    USE SIGNAL ;
    SHAPE ABUTMENT ;
    PORT
      LAYER M4 ;
      RECT 0.000 182.928 0.024 182.952 ;
    END
  END rd_out_A[41]
  PIN rd_out_B[41]
    DIRECTION OUTPUT ;
    USE SIGNAL ;
    SHAPE ABUTMENT ;
    PORT
      LAYER M4 ;
      RECT 103.336 182.928 103.360 182.952 ;
    END
  END rd_out_B[41]
  PIN rd_out_A[42]
    DIRECTION OUTPUT ;
    USE SIGNAL ;
    SHAPE ABUTMENT ;
    PORT
      LAYER M4 ;
      RECT 0.000 184.656 0.024 184.680 ;
    END
  END rd_out_A[42]
  PIN rd_out_B[42]
    DIRECTION OUTPUT ;
    USE SIGNAL ;
    SHAPE ABUTMENT ;
    PORT
      LAYER M4 ;
      RECT 103.336 184.656 103.360 184.680 ;
    END
  END rd_out_B[42]
  PIN rd_out_A[43]
    DIRECTION OUTPUT ;
    USE SIGNAL ;
    SHAPE ABUTMENT ;
    PORT
      LAYER M4 ;
      RECT 0.000 186.384 0.024 186.408 ;
    END
  END rd_out_A[43]
  PIN rd_out_B[43]
    DIRECTION OUTPUT ;
    USE SIGNAL ;
    SHAPE ABUTMENT ;
    PORT
      LAYER M4 ;
      RECT 103.336 186.384 103.360 186.408 ;
    END
  END rd_out_B[43]
  PIN rd_out_A[44]
    DIRECTION OUTPUT ;
    USE SIGNAL ;
    SHAPE ABUTMENT ;
    PORT
      LAYER M4 ;
      RECT 0.000 188.112 0.024 188.136 ;
    END
  END rd_out_A[44]
  PIN rd_out_B[44]
    DIRECTION OUTPUT ;
    USE SIGNAL ;
    SHAPE ABUTMENT ;
    PORT
      LAYER M4 ;
      RECT 103.336 188.112 103.360 188.136 ;
    END
  END rd_out_B[44]
  PIN rd_out_A[45]
    DIRECTION OUTPUT ;
    USE SIGNAL ;
    SHAPE ABUTMENT ;
    PORT
      LAYER M4 ;
      RECT 0.000 189.840 0.024 189.864 ;
    END
  END rd_out_A[45]
  PIN rd_out_B[45]
    DIRECTION OUTPUT ;
    USE SIGNAL ;
    SHAPE ABUTMENT ;
    PORT
      LAYER M4 ;
      RECT 103.336 189.840 103.360 189.864 ;
    END
  END rd_out_B[45]
  PIN rd_out_A[46]
    DIRECTION OUTPUT ;
    USE SIGNAL ;
    SHAPE ABUTMENT ;
    PORT
      LAYER M4 ;
      RECT 0.000 191.568 0.024 191.592 ;
    END
  END rd_out_A[46]
  PIN rd_out_B[46]
    DIRECTION OUTPUT ;
    USE SIGNAL ;
    SHAPE ABUTMENT ;
    PORT
      LAYER M4 ;
      RECT 103.336 191.568 103.360 191.592 ;
    END
  END rd_out_B[46]
  PIN rd_out_A[47]
    DIRECTION OUTPUT ;
    USE SIGNAL ;
    SHAPE ABUTMENT ;
    PORT
      LAYER M4 ;
      RECT 0.000 193.296 0.024 193.320 ;
    END
  END rd_out_A[47]
  PIN rd_out_B[47]
    DIRECTION OUTPUT ;
    USE SIGNAL ;
    SHAPE ABUTMENT ;
    PORT
      LAYER M4 ;
      RECT 103.336 193.296 103.360 193.320 ;
    END
  END rd_out_B[47]
  PIN rd_out_A[48]
    DIRECTION OUTPUT ;
    USE SIGNAL ;
    SHAPE ABUTMENT ;
    PORT
      LAYER M4 ;
      RECT 0.000 195.024 0.024 195.048 ;
    END
  END rd_out_A[48]
  PIN rd_out_B[48]
    DIRECTION OUTPUT ;
    USE SIGNAL ;
    SHAPE ABUTMENT ;
    PORT
      LAYER M4 ;
      RECT 103.336 195.024 103.360 195.048 ;
    END
  END rd_out_B[48]
  PIN rd_out_A[49]
    DIRECTION OUTPUT ;
    USE SIGNAL ;
    SHAPE ABUTMENT ;
    PORT
      LAYER M4 ;
      RECT 0.000 196.752 0.024 196.776 ;
    END
  END rd_out_A[49]
  PIN rd_out_B[49]
    DIRECTION OUTPUT ;
    USE SIGNAL ;
    SHAPE ABUTMENT ;
    PORT
      LAYER M4 ;
      RECT 103.336 196.752 103.360 196.776 ;
    END
  END rd_out_B[49]
  PIN rd_out_A[50]
    DIRECTION OUTPUT ;
    USE SIGNAL ;
    SHAPE ABUTMENT ;
    PORT
      LAYER M4 ;
      RECT 0.000 198.480 0.024 198.504 ;
    END
  END rd_out_A[50]
  PIN rd_out_B[50]
    DIRECTION OUTPUT ;
    USE SIGNAL ;
    SHAPE ABUTMENT ;
    PORT
      LAYER M4 ;
      RECT 103.336 198.480 103.360 198.504 ;
    END
  END rd_out_B[50]
  PIN rd_out_A[51]
    DIRECTION OUTPUT ;
    USE SIGNAL ;
    SHAPE ABUTMENT ;
    PORT
      LAYER M4 ;
      RECT 0.000 200.208 0.024 200.232 ;
    END
  END rd_out_A[51]
  PIN rd_out_B[51]
    DIRECTION OUTPUT ;
    USE SIGNAL ;
    SHAPE ABUTMENT ;
    PORT
      LAYER M4 ;
      RECT 103.336 200.208 103.360 200.232 ;
    END
  END rd_out_B[51]
  PIN rd_out_A[52]
    DIRECTION OUTPUT ;
    USE SIGNAL ;
    SHAPE ABUTMENT ;
    PORT
      LAYER M4 ;
      RECT 0.000 201.936 0.024 201.960 ;
    END
  END rd_out_A[52]
  PIN rd_out_B[52]
    DIRECTION OUTPUT ;
    USE SIGNAL ;
    SHAPE ABUTMENT ;
    PORT
      LAYER M4 ;
      RECT 103.336 201.936 103.360 201.960 ;
    END
  END rd_out_B[52]
  PIN rd_out_A[53]
    DIRECTION OUTPUT ;
    USE SIGNAL ;
    SHAPE ABUTMENT ;
    PORT
      LAYER M4 ;
      RECT 0.000 203.664 0.024 203.688 ;
    END
  END rd_out_A[53]
  PIN rd_out_B[53]
    DIRECTION OUTPUT ;
    USE SIGNAL ;
    SHAPE ABUTMENT ;
    PORT
      LAYER M4 ;
      RECT 103.336 203.664 103.360 203.688 ;
    END
  END rd_out_B[53]
  PIN rd_out_A[54]
    DIRECTION OUTPUT ;
    USE SIGNAL ;
    SHAPE ABUTMENT ;
    PORT
      LAYER M4 ;
      RECT 0.000 205.392 0.024 205.416 ;
    END
  END rd_out_A[54]
  PIN rd_out_B[54]
    DIRECTION OUTPUT ;
    USE SIGNAL ;
    SHAPE ABUTMENT ;
    PORT
      LAYER M4 ;
      RECT 103.336 205.392 103.360 205.416 ;
    END
  END rd_out_B[54]
  PIN rd_out_A[55]
    DIRECTION OUTPUT ;
    USE SIGNAL ;
    SHAPE ABUTMENT ;
    PORT
      LAYER M4 ;
      RECT 0.000 207.120 0.024 207.144 ;
    END
  END rd_out_A[55]
  PIN rd_out_B[55]
    DIRECTION OUTPUT ;
    USE SIGNAL ;
    SHAPE ABUTMENT ;
    PORT
      LAYER M4 ;
      RECT 103.336 207.120 103.360 207.144 ;
    END
  END rd_out_B[55]
  PIN rd_out_A[56]
    DIRECTION OUTPUT ;
    USE SIGNAL ;
    SHAPE ABUTMENT ;
    PORT
      LAYER M4 ;
      RECT 0.000 208.848 0.024 208.872 ;
    END
  END rd_out_A[56]
  PIN rd_out_B[56]
    DIRECTION OUTPUT ;
    USE SIGNAL ;
    SHAPE ABUTMENT ;
    PORT
      LAYER M4 ;
      RECT 103.336 208.848 103.360 208.872 ;
    END
  END rd_out_B[56]
  PIN rd_out_A[57]
    DIRECTION OUTPUT ;
    USE SIGNAL ;
    SHAPE ABUTMENT ;
    PORT
      LAYER M4 ;
      RECT 0.000 210.576 0.024 210.600 ;
    END
  END rd_out_A[57]
  PIN rd_out_B[57]
    DIRECTION OUTPUT ;
    USE SIGNAL ;
    SHAPE ABUTMENT ;
    PORT
      LAYER M4 ;
      RECT 103.336 210.576 103.360 210.600 ;
    END
  END rd_out_B[57]
  PIN rd_out_A[58]
    DIRECTION OUTPUT ;
    USE SIGNAL ;
    SHAPE ABUTMENT ;
    PORT
      LAYER M4 ;
      RECT 0.000 212.304 0.024 212.328 ;
    END
  END rd_out_A[58]
  PIN rd_out_B[58]
    DIRECTION OUTPUT ;
    USE SIGNAL ;
    SHAPE ABUTMENT ;
    PORT
      LAYER M4 ;
      RECT 103.336 212.304 103.360 212.328 ;
    END
  END rd_out_B[58]
  PIN rd_out_A[59]
    DIRECTION OUTPUT ;
    USE SIGNAL ;
    SHAPE ABUTMENT ;
    PORT
      LAYER M4 ;
      RECT 0.000 214.032 0.024 214.056 ;
    END
  END rd_out_A[59]
  PIN rd_out_B[59]
    DIRECTION OUTPUT ;
    USE SIGNAL ;
    SHAPE ABUTMENT ;
    PORT
      LAYER M4 ;
      RECT 103.336 214.032 103.360 214.056 ;
    END
  END rd_out_B[59]
  PIN rd_out_A[60]
    DIRECTION OUTPUT ;
    USE SIGNAL ;
    SHAPE ABUTMENT ;
    PORT
      LAYER M4 ;
      RECT 0.000 215.760 0.024 215.784 ;
    END
  END rd_out_A[60]
  PIN rd_out_B[60]
    DIRECTION OUTPUT ;
    USE SIGNAL ;
    SHAPE ABUTMENT ;
    PORT
      LAYER M4 ;
      RECT 103.336 215.760 103.360 215.784 ;
    END
  END rd_out_B[60]
  PIN rd_out_A[61]
    DIRECTION OUTPUT ;
    USE SIGNAL ;
    SHAPE ABUTMENT ;
    PORT
      LAYER M4 ;
      RECT 0.000 217.488 0.024 217.512 ;
    END
  END rd_out_A[61]
  PIN rd_out_B[61]
    DIRECTION OUTPUT ;
    USE SIGNAL ;
    SHAPE ABUTMENT ;
    PORT
      LAYER M4 ;
      RECT 103.336 217.488 103.360 217.512 ;
    END
  END rd_out_B[61]
  PIN rd_out_A[62]
    DIRECTION OUTPUT ;
    USE SIGNAL ;
    SHAPE ABUTMENT ;
    PORT
      LAYER M4 ;
      RECT 0.000 219.216 0.024 219.240 ;
    END
  END rd_out_A[62]
  PIN rd_out_B[62]
    DIRECTION OUTPUT ;
    USE SIGNAL ;
    SHAPE ABUTMENT ;
    PORT
      LAYER M4 ;
      RECT 103.336 219.216 103.360 219.240 ;
    END
  END rd_out_B[62]
  PIN rd_out_A[63]
    DIRECTION OUTPUT ;
    USE SIGNAL ;
    SHAPE ABUTMENT ;
    PORT
      LAYER M4 ;
      RECT 0.000 220.944 0.024 220.968 ;
    END
  END rd_out_A[63]
  PIN rd_out_B[63]
    DIRECTION OUTPUT ;
    USE SIGNAL ;
    SHAPE ABUTMENT ;
    PORT
      LAYER M4 ;
      RECT 103.336 220.944 103.360 220.968 ;
    END
  END rd_out_B[63]
  PIN wd_in_A[0]
    DIRECTION INPUT ;
    USE SIGNAL ;
    SHAPE ABUTMENT ;
    PORT
      LAYER M4 ;
      RECT 0.000 224.112 0.024 224.136 ;
    END
  END wd_in_A[0]
  PIN wd_in_B[0]
    DIRECTION INPUT ;
    USE SIGNAL ;
    SHAPE ABUTMENT ;
    PORT
      LAYER M4 ;
      RECT 103.336 224.112 103.360 224.136 ;
    END
  END wd_in_B[0]
  PIN wd_in_A[1]
    DIRECTION INPUT ;
    USE SIGNAL ;
    SHAPE ABUTMENT ;
    PORT
      LAYER M4 ;
      RECT 0.000 225.840 0.024 225.864 ;
    END
  END wd_in_A[1]
  PIN wd_in_B[1]
    DIRECTION INPUT ;
    USE SIGNAL ;
    SHAPE ABUTMENT ;
    PORT
      LAYER M4 ;
      RECT 103.336 225.840 103.360 225.864 ;
    END
  END wd_in_B[1]
  PIN wd_in_A[2]
    DIRECTION INPUT ;
    USE SIGNAL ;
    SHAPE ABUTMENT ;
    PORT
      LAYER M4 ;
      RECT 0.000 227.568 0.024 227.592 ;
    END
  END wd_in_A[2]
  PIN wd_in_B[2]
    DIRECTION INPUT ;
    USE SIGNAL ;
    SHAPE ABUTMENT ;
    PORT
      LAYER M4 ;
      RECT 103.336 227.568 103.360 227.592 ;
    END
  END wd_in_B[2]
  PIN wd_in_A[3]
    DIRECTION INPUT ;
    USE SIGNAL ;
    SHAPE ABUTMENT ;
    PORT
      LAYER M4 ;
      RECT 0.000 229.296 0.024 229.320 ;
    END
  END wd_in_A[3]
  PIN wd_in_B[3]
    DIRECTION INPUT ;
    USE SIGNAL ;
    SHAPE ABUTMENT ;
    PORT
      LAYER M4 ;
      RECT 103.336 229.296 103.360 229.320 ;
    END
  END wd_in_B[3]
  PIN wd_in_A[4]
    DIRECTION INPUT ;
    USE SIGNAL ;
    SHAPE ABUTMENT ;
    PORT
      LAYER M4 ;
      RECT 0.000 231.024 0.024 231.048 ;
    END
  END wd_in_A[4]
  PIN wd_in_B[4]
    DIRECTION INPUT ;
    USE SIGNAL ;
    SHAPE ABUTMENT ;
    PORT
      LAYER M4 ;
      RECT 103.336 231.024 103.360 231.048 ;
    END
  END wd_in_B[4]
  PIN wd_in_A[5]
    DIRECTION INPUT ;
    USE SIGNAL ;
    SHAPE ABUTMENT ;
    PORT
      LAYER M4 ;
      RECT 0.000 232.752 0.024 232.776 ;
    END
  END wd_in_A[5]
  PIN wd_in_B[5]
    DIRECTION INPUT ;
    USE SIGNAL ;
    SHAPE ABUTMENT ;
    PORT
      LAYER M4 ;
      RECT 103.336 232.752 103.360 232.776 ;
    END
  END wd_in_B[5]
  PIN wd_in_A[6]
    DIRECTION INPUT ;
    USE SIGNAL ;
    SHAPE ABUTMENT ;
    PORT
      LAYER M4 ;
      RECT 0.000 234.480 0.024 234.504 ;
    END
  END wd_in_A[6]
  PIN wd_in_B[6]
    DIRECTION INPUT ;
    USE SIGNAL ;
    SHAPE ABUTMENT ;
    PORT
      LAYER M4 ;
      RECT 103.336 234.480 103.360 234.504 ;
    END
  END wd_in_B[6]
  PIN wd_in_A[7]
    DIRECTION INPUT ;
    USE SIGNAL ;
    SHAPE ABUTMENT ;
    PORT
      LAYER M4 ;
      RECT 0.000 236.208 0.024 236.232 ;
    END
  END wd_in_A[7]
  PIN wd_in_B[7]
    DIRECTION INPUT ;
    USE SIGNAL ;
    SHAPE ABUTMENT ;
    PORT
      LAYER M4 ;
      RECT 103.336 236.208 103.360 236.232 ;
    END
  END wd_in_B[7]
  PIN wd_in_A[8]
    DIRECTION INPUT ;
    USE SIGNAL ;
    SHAPE ABUTMENT ;
    PORT
      LAYER M4 ;
      RECT 0.000 237.936 0.024 237.960 ;
    END
  END wd_in_A[8]
  PIN wd_in_B[8]
    DIRECTION INPUT ;
    USE SIGNAL ;
    SHAPE ABUTMENT ;
    PORT
      LAYER M4 ;
      RECT 103.336 237.936 103.360 237.960 ;
    END
  END wd_in_B[8]
  PIN wd_in_A[9]
    DIRECTION INPUT ;
    USE SIGNAL ;
    SHAPE ABUTMENT ;
    PORT
      LAYER M4 ;
      RECT 0.000 239.664 0.024 239.688 ;
    END
  END wd_in_A[9]
  PIN wd_in_B[9]
    DIRECTION INPUT ;
    USE SIGNAL ;
    SHAPE ABUTMENT ;
    PORT
      LAYER M4 ;
      RECT 103.336 239.664 103.360 239.688 ;
    END
  END wd_in_B[9]
  PIN wd_in_A[10]
    DIRECTION INPUT ;
    USE SIGNAL ;
    SHAPE ABUTMENT ;
    PORT
      LAYER M4 ;
      RECT 0.000 241.392 0.024 241.416 ;
    END
  END wd_in_A[10]
  PIN wd_in_B[10]
    DIRECTION INPUT ;
    USE SIGNAL ;
    SHAPE ABUTMENT ;
    PORT
      LAYER M4 ;
      RECT 103.336 241.392 103.360 241.416 ;
    END
  END wd_in_B[10]
  PIN wd_in_A[11]
    DIRECTION INPUT ;
    USE SIGNAL ;
    SHAPE ABUTMENT ;
    PORT
      LAYER M4 ;
      RECT 0.000 243.120 0.024 243.144 ;
    END
  END wd_in_A[11]
  PIN wd_in_B[11]
    DIRECTION INPUT ;
    USE SIGNAL ;
    SHAPE ABUTMENT ;
    PORT
      LAYER M4 ;
      RECT 103.336 243.120 103.360 243.144 ;
    END
  END wd_in_B[11]
  PIN wd_in_A[12]
    DIRECTION INPUT ;
    USE SIGNAL ;
    SHAPE ABUTMENT ;
    PORT
      LAYER M4 ;
      RECT 0.000 244.848 0.024 244.872 ;
    END
  END wd_in_A[12]
  PIN wd_in_B[12]
    DIRECTION INPUT ;
    USE SIGNAL ;
    SHAPE ABUTMENT ;
    PORT
      LAYER M4 ;
      RECT 103.336 244.848 103.360 244.872 ;
    END
  END wd_in_B[12]
  PIN wd_in_A[13]
    DIRECTION INPUT ;
    USE SIGNAL ;
    SHAPE ABUTMENT ;
    PORT
      LAYER M4 ;
      RECT 0.000 246.576 0.024 246.600 ;
    END
  END wd_in_A[13]
  PIN wd_in_B[13]
    DIRECTION INPUT ;
    USE SIGNAL ;
    SHAPE ABUTMENT ;
    PORT
      LAYER M4 ;
      RECT 103.336 246.576 103.360 246.600 ;
    END
  END wd_in_B[13]
  PIN wd_in_A[14]
    DIRECTION INPUT ;
    USE SIGNAL ;
    SHAPE ABUTMENT ;
    PORT
      LAYER M4 ;
      RECT 0.000 248.304 0.024 248.328 ;
    END
  END wd_in_A[14]
  PIN wd_in_B[14]
    DIRECTION INPUT ;
    USE SIGNAL ;
    SHAPE ABUTMENT ;
    PORT
      LAYER M4 ;
      RECT 103.336 248.304 103.360 248.328 ;
    END
  END wd_in_B[14]
  PIN wd_in_A[15]
    DIRECTION INPUT ;
    USE SIGNAL ;
    SHAPE ABUTMENT ;
    PORT
      LAYER M4 ;
      RECT 0.000 250.032 0.024 250.056 ;
    END
  END wd_in_A[15]
  PIN wd_in_B[15]
    DIRECTION INPUT ;
    USE SIGNAL ;
    SHAPE ABUTMENT ;
    PORT
      LAYER M4 ;
      RECT 103.336 250.032 103.360 250.056 ;
    END
  END wd_in_B[15]
  PIN wd_in_A[16]
    DIRECTION INPUT ;
    USE SIGNAL ;
    SHAPE ABUTMENT ;
    PORT
      LAYER M4 ;
      RECT 0.000 251.760 0.024 251.784 ;
    END
  END wd_in_A[16]
  PIN wd_in_B[16]
    DIRECTION INPUT ;
    USE SIGNAL ;
    SHAPE ABUTMENT ;
    PORT
      LAYER M4 ;
      RECT 103.336 251.760 103.360 251.784 ;
    END
  END wd_in_B[16]
  PIN wd_in_A[17]
    DIRECTION INPUT ;
    USE SIGNAL ;
    SHAPE ABUTMENT ;
    PORT
      LAYER M4 ;
      RECT 0.000 253.488 0.024 253.512 ;
    END
  END wd_in_A[17]
  PIN wd_in_B[17]
    DIRECTION INPUT ;
    USE SIGNAL ;
    SHAPE ABUTMENT ;
    PORT
      LAYER M4 ;
      RECT 103.336 253.488 103.360 253.512 ;
    END
  END wd_in_B[17]
  PIN wd_in_A[18]
    DIRECTION INPUT ;
    USE SIGNAL ;
    SHAPE ABUTMENT ;
    PORT
      LAYER M4 ;
      RECT 0.000 255.216 0.024 255.240 ;
    END
  END wd_in_A[18]
  PIN wd_in_B[18]
    DIRECTION INPUT ;
    USE SIGNAL ;
    SHAPE ABUTMENT ;
    PORT
      LAYER M4 ;
      RECT 103.336 255.216 103.360 255.240 ;
    END
  END wd_in_B[18]
  PIN wd_in_A[19]
    DIRECTION INPUT ;
    USE SIGNAL ;
    SHAPE ABUTMENT ;
    PORT
      LAYER M4 ;
      RECT 0.000 256.944 0.024 256.968 ;
    END
  END wd_in_A[19]
  PIN wd_in_B[19]
    DIRECTION INPUT ;
    USE SIGNAL ;
    SHAPE ABUTMENT ;
    PORT
      LAYER M4 ;
      RECT 103.336 256.944 103.360 256.968 ;
    END
  END wd_in_B[19]
  PIN wd_in_A[20]
    DIRECTION INPUT ;
    USE SIGNAL ;
    SHAPE ABUTMENT ;
    PORT
      LAYER M4 ;
      RECT 0.000 258.672 0.024 258.696 ;
    END
  END wd_in_A[20]
  PIN wd_in_B[20]
    DIRECTION INPUT ;
    USE SIGNAL ;
    SHAPE ABUTMENT ;
    PORT
      LAYER M4 ;
      RECT 103.336 258.672 103.360 258.696 ;
    END
  END wd_in_B[20]
  PIN wd_in_A[21]
    DIRECTION INPUT ;
    USE SIGNAL ;
    SHAPE ABUTMENT ;
    PORT
      LAYER M4 ;
      RECT 0.000 260.400 0.024 260.424 ;
    END
  END wd_in_A[21]
  PIN wd_in_B[21]
    DIRECTION INPUT ;
    USE SIGNAL ;
    SHAPE ABUTMENT ;
    PORT
      LAYER M4 ;
      RECT 103.336 260.400 103.360 260.424 ;
    END
  END wd_in_B[21]
  PIN wd_in_A[22]
    DIRECTION INPUT ;
    USE SIGNAL ;
    SHAPE ABUTMENT ;
    PORT
      LAYER M4 ;
      RECT 0.000 262.128 0.024 262.152 ;
    END
  END wd_in_A[22]
  PIN wd_in_B[22]
    DIRECTION INPUT ;
    USE SIGNAL ;
    SHAPE ABUTMENT ;
    PORT
      LAYER M4 ;
      RECT 103.336 262.128 103.360 262.152 ;
    END
  END wd_in_B[22]
  PIN wd_in_A[23]
    DIRECTION INPUT ;
    USE SIGNAL ;
    SHAPE ABUTMENT ;
    PORT
      LAYER M4 ;
      RECT 0.000 263.856 0.024 263.880 ;
    END
  END wd_in_A[23]
  PIN wd_in_B[23]
    DIRECTION INPUT ;
    USE SIGNAL ;
    SHAPE ABUTMENT ;
    PORT
      LAYER M4 ;
      RECT 103.336 263.856 103.360 263.880 ;
    END
  END wd_in_B[23]
  PIN wd_in_A[24]
    DIRECTION INPUT ;
    USE SIGNAL ;
    SHAPE ABUTMENT ;
    PORT
      LAYER M4 ;
      RECT 0.000 265.584 0.024 265.608 ;
    END
  END wd_in_A[24]
  PIN wd_in_B[24]
    DIRECTION INPUT ;
    USE SIGNAL ;
    SHAPE ABUTMENT ;
    PORT
      LAYER M4 ;
      RECT 103.336 265.584 103.360 265.608 ;
    END
  END wd_in_B[24]
  PIN wd_in_A[25]
    DIRECTION INPUT ;
    USE SIGNAL ;
    SHAPE ABUTMENT ;
    PORT
      LAYER M4 ;
      RECT 0.000 267.312 0.024 267.336 ;
    END
  END wd_in_A[25]
  PIN wd_in_B[25]
    DIRECTION INPUT ;
    USE SIGNAL ;
    SHAPE ABUTMENT ;
    PORT
      LAYER M4 ;
      RECT 103.336 267.312 103.360 267.336 ;
    END
  END wd_in_B[25]
  PIN wd_in_A[26]
    DIRECTION INPUT ;
    USE SIGNAL ;
    SHAPE ABUTMENT ;
    PORT
      LAYER M4 ;
      RECT 0.000 269.040 0.024 269.064 ;
    END
  END wd_in_A[26]
  PIN wd_in_B[26]
    DIRECTION INPUT ;
    USE SIGNAL ;
    SHAPE ABUTMENT ;
    PORT
      LAYER M4 ;
      RECT 103.336 269.040 103.360 269.064 ;
    END
  END wd_in_B[26]
  PIN wd_in_A[27]
    DIRECTION INPUT ;
    USE SIGNAL ;
    SHAPE ABUTMENT ;
    PORT
      LAYER M4 ;
      RECT 0.000 270.768 0.024 270.792 ;
    END
  END wd_in_A[27]
  PIN wd_in_B[27]
    DIRECTION INPUT ;
    USE SIGNAL ;
    SHAPE ABUTMENT ;
    PORT
      LAYER M4 ;
      RECT 103.336 270.768 103.360 270.792 ;
    END
  END wd_in_B[27]
  PIN wd_in_A[28]
    DIRECTION INPUT ;
    USE SIGNAL ;
    SHAPE ABUTMENT ;
    PORT
      LAYER M4 ;
      RECT 0.000 272.496 0.024 272.520 ;
    END
  END wd_in_A[28]
  PIN wd_in_B[28]
    DIRECTION INPUT ;
    USE SIGNAL ;
    SHAPE ABUTMENT ;
    PORT
      LAYER M4 ;
      RECT 103.336 272.496 103.360 272.520 ;
    END
  END wd_in_B[28]
  PIN wd_in_A[29]
    DIRECTION INPUT ;
    USE SIGNAL ;
    SHAPE ABUTMENT ;
    PORT
      LAYER M4 ;
      RECT 0.000 274.224 0.024 274.248 ;
    END
  END wd_in_A[29]
  PIN wd_in_B[29]
    DIRECTION INPUT ;
    USE SIGNAL ;
    SHAPE ABUTMENT ;
    PORT
      LAYER M4 ;
      RECT 103.336 274.224 103.360 274.248 ;
    END
  END wd_in_B[29]
  PIN wd_in_A[30]
    DIRECTION INPUT ;
    USE SIGNAL ;
    SHAPE ABUTMENT ;
    PORT
      LAYER M4 ;
      RECT 0.000 275.952 0.024 275.976 ;
    END
  END wd_in_A[30]
  PIN wd_in_B[30]
    DIRECTION INPUT ;
    USE SIGNAL ;
    SHAPE ABUTMENT ;
    PORT
      LAYER M4 ;
      RECT 103.336 275.952 103.360 275.976 ;
    END
  END wd_in_B[30]
  PIN wd_in_A[31]
    DIRECTION INPUT ;
    USE SIGNAL ;
    SHAPE ABUTMENT ;
    PORT
      LAYER M4 ;
      RECT 0.000 277.680 0.024 277.704 ;
    END
  END wd_in_A[31]
  PIN wd_in_B[31]
    DIRECTION INPUT ;
    USE SIGNAL ;
    SHAPE ABUTMENT ;
    PORT
      LAYER M4 ;
      RECT 103.336 277.680 103.360 277.704 ;
    END
  END wd_in_B[31]
  PIN wd_in_A[32]
    DIRECTION INPUT ;
    USE SIGNAL ;
    SHAPE ABUTMENT ;
    PORT
      LAYER M4 ;
      RECT 0.000 279.408 0.024 279.432 ;
    END
  END wd_in_A[32]
  PIN wd_in_B[32]
    DIRECTION INPUT ;
    USE SIGNAL ;
    SHAPE ABUTMENT ;
    PORT
      LAYER M4 ;
      RECT 103.336 279.408 103.360 279.432 ;
    END
  END wd_in_B[32]
  PIN wd_in_A[33]
    DIRECTION INPUT ;
    USE SIGNAL ;
    SHAPE ABUTMENT ;
    PORT
      LAYER M4 ;
      RECT 0.000 281.136 0.024 281.160 ;
    END
  END wd_in_A[33]
  PIN wd_in_B[33]
    DIRECTION INPUT ;
    USE SIGNAL ;
    SHAPE ABUTMENT ;
    PORT
      LAYER M4 ;
      RECT 103.336 281.136 103.360 281.160 ;
    END
  END wd_in_B[33]
  PIN wd_in_A[34]
    DIRECTION INPUT ;
    USE SIGNAL ;
    SHAPE ABUTMENT ;
    PORT
      LAYER M4 ;
      RECT 0.000 282.864 0.024 282.888 ;
    END
  END wd_in_A[34]
  PIN wd_in_B[34]
    DIRECTION INPUT ;
    USE SIGNAL ;
    SHAPE ABUTMENT ;
    PORT
      LAYER M4 ;
      RECT 103.336 282.864 103.360 282.888 ;
    END
  END wd_in_B[34]
  PIN wd_in_A[35]
    DIRECTION INPUT ;
    USE SIGNAL ;
    SHAPE ABUTMENT ;
    PORT
      LAYER M4 ;
      RECT 0.000 284.592 0.024 284.616 ;
    END
  END wd_in_A[35]
  PIN wd_in_B[35]
    DIRECTION INPUT ;
    USE SIGNAL ;
    SHAPE ABUTMENT ;
    PORT
      LAYER M4 ;
      RECT 103.336 284.592 103.360 284.616 ;
    END
  END wd_in_B[35]
  PIN wd_in_A[36]
    DIRECTION INPUT ;
    USE SIGNAL ;
    SHAPE ABUTMENT ;
    PORT
      LAYER M4 ;
      RECT 0.000 286.320 0.024 286.344 ;
    END
  END wd_in_A[36]
  PIN wd_in_B[36]
    DIRECTION INPUT ;
    USE SIGNAL ;
    SHAPE ABUTMENT ;
    PORT
      LAYER M4 ;
      RECT 103.336 286.320 103.360 286.344 ;
    END
  END wd_in_B[36]
  PIN wd_in_A[37]
    DIRECTION INPUT ;
    USE SIGNAL ;
    SHAPE ABUTMENT ;
    PORT
      LAYER M4 ;
      RECT 0.000 288.048 0.024 288.072 ;
    END
  END wd_in_A[37]
  PIN wd_in_B[37]
    DIRECTION INPUT ;
    USE SIGNAL ;
    SHAPE ABUTMENT ;
    PORT
      LAYER M4 ;
      RECT 103.336 288.048 103.360 288.072 ;
    END
  END wd_in_B[37]
  PIN wd_in_A[38]
    DIRECTION INPUT ;
    USE SIGNAL ;
    SHAPE ABUTMENT ;
    PORT
      LAYER M4 ;
      RECT 0.000 289.776 0.024 289.800 ;
    END
  END wd_in_A[38]
  PIN wd_in_B[38]
    DIRECTION INPUT ;
    USE SIGNAL ;
    SHAPE ABUTMENT ;
    PORT
      LAYER M4 ;
      RECT 103.336 289.776 103.360 289.800 ;
    END
  END wd_in_B[38]
  PIN wd_in_A[39]
    DIRECTION INPUT ;
    USE SIGNAL ;
    SHAPE ABUTMENT ;
    PORT
      LAYER M4 ;
      RECT 0.000 291.504 0.024 291.528 ;
    END
  END wd_in_A[39]
  PIN wd_in_B[39]
    DIRECTION INPUT ;
    USE SIGNAL ;
    SHAPE ABUTMENT ;
    PORT
      LAYER M4 ;
      RECT 103.336 291.504 103.360 291.528 ;
    END
  END wd_in_B[39]
  PIN wd_in_A[40]
    DIRECTION INPUT ;
    USE SIGNAL ;
    SHAPE ABUTMENT ;
    PORT
      LAYER M4 ;
      RECT 0.000 293.232 0.024 293.256 ;
    END
  END wd_in_A[40]
  PIN wd_in_B[40]
    DIRECTION INPUT ;
    USE SIGNAL ;
    SHAPE ABUTMENT ;
    PORT
      LAYER M4 ;
      RECT 103.336 293.232 103.360 293.256 ;
    END
  END wd_in_B[40]
  PIN wd_in_A[41]
    DIRECTION INPUT ;
    USE SIGNAL ;
    SHAPE ABUTMENT ;
    PORT
      LAYER M4 ;
      RECT 0.000 294.960 0.024 294.984 ;
    END
  END wd_in_A[41]
  PIN wd_in_B[41]
    DIRECTION INPUT ;
    USE SIGNAL ;
    SHAPE ABUTMENT ;
    PORT
      LAYER M4 ;
      RECT 103.336 294.960 103.360 294.984 ;
    END
  END wd_in_B[41]
  PIN wd_in_A[42]
    DIRECTION INPUT ;
    USE SIGNAL ;
    SHAPE ABUTMENT ;
    PORT
      LAYER M4 ;
      RECT 0.000 296.688 0.024 296.712 ;
    END
  END wd_in_A[42]
  PIN wd_in_B[42]
    DIRECTION INPUT ;
    USE SIGNAL ;
    SHAPE ABUTMENT ;
    PORT
      LAYER M4 ;
      RECT 103.336 296.688 103.360 296.712 ;
    END
  END wd_in_B[42]
  PIN wd_in_A[43]
    DIRECTION INPUT ;
    USE SIGNAL ;
    SHAPE ABUTMENT ;
    PORT
      LAYER M4 ;
      RECT 0.000 298.416 0.024 298.440 ;
    END
  END wd_in_A[43]
  PIN wd_in_B[43]
    DIRECTION INPUT ;
    USE SIGNAL ;
    SHAPE ABUTMENT ;
    PORT
      LAYER M4 ;
      RECT 103.336 298.416 103.360 298.440 ;
    END
  END wd_in_B[43]
  PIN wd_in_A[44]
    DIRECTION INPUT ;
    USE SIGNAL ;
    SHAPE ABUTMENT ;
    PORT
      LAYER M4 ;
      RECT 0.000 300.144 0.024 300.168 ;
    END
  END wd_in_A[44]
  PIN wd_in_B[44]
    DIRECTION INPUT ;
    USE SIGNAL ;
    SHAPE ABUTMENT ;
    PORT
      LAYER M4 ;
      RECT 103.336 300.144 103.360 300.168 ;
    END
  END wd_in_B[44]
  PIN wd_in_A[45]
    DIRECTION INPUT ;
    USE SIGNAL ;
    SHAPE ABUTMENT ;
    PORT
      LAYER M4 ;
      RECT 0.000 301.872 0.024 301.896 ;
    END
  END wd_in_A[45]
  PIN wd_in_B[45]
    DIRECTION INPUT ;
    USE SIGNAL ;
    SHAPE ABUTMENT ;
    PORT
      LAYER M4 ;
      RECT 103.336 301.872 103.360 301.896 ;
    END
  END wd_in_B[45]
  PIN wd_in_A[46]
    DIRECTION INPUT ;
    USE SIGNAL ;
    SHAPE ABUTMENT ;
    PORT
      LAYER M4 ;
      RECT 0.000 303.600 0.024 303.624 ;
    END
  END wd_in_A[46]
  PIN wd_in_B[46]
    DIRECTION INPUT ;
    USE SIGNAL ;
    SHAPE ABUTMENT ;
    PORT
      LAYER M4 ;
      RECT 103.336 303.600 103.360 303.624 ;
    END
  END wd_in_B[46]
  PIN wd_in_A[47]
    DIRECTION INPUT ;
    USE SIGNAL ;
    SHAPE ABUTMENT ;
    PORT
      LAYER M4 ;
      RECT 0.000 305.328 0.024 305.352 ;
    END
  END wd_in_A[47]
  PIN wd_in_B[47]
    DIRECTION INPUT ;
    USE SIGNAL ;
    SHAPE ABUTMENT ;
    PORT
      LAYER M4 ;
      RECT 103.336 305.328 103.360 305.352 ;
    END
  END wd_in_B[47]
  PIN wd_in_A[48]
    DIRECTION INPUT ;
    USE SIGNAL ;
    SHAPE ABUTMENT ;
    PORT
      LAYER M4 ;
      RECT 0.000 307.056 0.024 307.080 ;
    END
  END wd_in_A[48]
  PIN wd_in_B[48]
    DIRECTION INPUT ;
    USE SIGNAL ;
    SHAPE ABUTMENT ;
    PORT
      LAYER M4 ;
      RECT 103.336 307.056 103.360 307.080 ;
    END
  END wd_in_B[48]
  PIN wd_in_A[49]
    DIRECTION INPUT ;
    USE SIGNAL ;
    SHAPE ABUTMENT ;
    PORT
      LAYER M4 ;
      RECT 0.000 308.784 0.024 308.808 ;
    END
  END wd_in_A[49]
  PIN wd_in_B[49]
    DIRECTION INPUT ;
    USE SIGNAL ;
    SHAPE ABUTMENT ;
    PORT
      LAYER M4 ;
      RECT 103.336 308.784 103.360 308.808 ;
    END
  END wd_in_B[49]
  PIN wd_in_A[50]
    DIRECTION INPUT ;
    USE SIGNAL ;
    SHAPE ABUTMENT ;
    PORT
      LAYER M4 ;
      RECT 0.000 310.512 0.024 310.536 ;
    END
  END wd_in_A[50]
  PIN wd_in_B[50]
    DIRECTION INPUT ;
    USE SIGNAL ;
    SHAPE ABUTMENT ;
    PORT
      LAYER M4 ;
      RECT 103.336 310.512 103.360 310.536 ;
    END
  END wd_in_B[50]
  PIN wd_in_A[51]
    DIRECTION INPUT ;
    USE SIGNAL ;
    SHAPE ABUTMENT ;
    PORT
      LAYER M4 ;
      RECT 0.000 312.240 0.024 312.264 ;
    END
  END wd_in_A[51]
  PIN wd_in_B[51]
    DIRECTION INPUT ;
    USE SIGNAL ;
    SHAPE ABUTMENT ;
    PORT
      LAYER M4 ;
      RECT 103.336 312.240 103.360 312.264 ;
    END
  END wd_in_B[51]
  PIN wd_in_A[52]
    DIRECTION INPUT ;
    USE SIGNAL ;
    SHAPE ABUTMENT ;
    PORT
      LAYER M4 ;
      RECT 0.000 313.968 0.024 313.992 ;
    END
  END wd_in_A[52]
  PIN wd_in_B[52]
    DIRECTION INPUT ;
    USE SIGNAL ;
    SHAPE ABUTMENT ;
    PORT
      LAYER M4 ;
      RECT 103.336 313.968 103.360 313.992 ;
    END
  END wd_in_B[52]
  PIN wd_in_A[53]
    DIRECTION INPUT ;
    USE SIGNAL ;
    SHAPE ABUTMENT ;
    PORT
      LAYER M4 ;
      RECT 0.000 315.696 0.024 315.720 ;
    END
  END wd_in_A[53]
  PIN wd_in_B[53]
    DIRECTION INPUT ;
    USE SIGNAL ;
    SHAPE ABUTMENT ;
    PORT
      LAYER M4 ;
      RECT 103.336 315.696 103.360 315.720 ;
    END
  END wd_in_B[53]
  PIN wd_in_A[54]
    DIRECTION INPUT ;
    USE SIGNAL ;
    SHAPE ABUTMENT ;
    PORT
      LAYER M4 ;
      RECT 0.000 317.424 0.024 317.448 ;
    END
  END wd_in_A[54]
  PIN wd_in_B[54]
    DIRECTION INPUT ;
    USE SIGNAL ;
    SHAPE ABUTMENT ;
    PORT
      LAYER M4 ;
      RECT 103.336 317.424 103.360 317.448 ;
    END
  END wd_in_B[54]
  PIN wd_in_A[55]
    DIRECTION INPUT ;
    USE SIGNAL ;
    SHAPE ABUTMENT ;
    PORT
      LAYER M4 ;
      RECT 0.000 319.152 0.024 319.176 ;
    END
  END wd_in_A[55]
  PIN wd_in_B[55]
    DIRECTION INPUT ;
    USE SIGNAL ;
    SHAPE ABUTMENT ;
    PORT
      LAYER M4 ;
      RECT 103.336 319.152 103.360 319.176 ;
    END
  END wd_in_B[55]
  PIN wd_in_A[56]
    DIRECTION INPUT ;
    USE SIGNAL ;
    SHAPE ABUTMENT ;
    PORT
      LAYER M4 ;
      RECT 0.000 320.880 0.024 320.904 ;
    END
  END wd_in_A[56]
  PIN wd_in_B[56]
    DIRECTION INPUT ;
    USE SIGNAL ;
    SHAPE ABUTMENT ;
    PORT
      LAYER M4 ;
      RECT 103.336 320.880 103.360 320.904 ;
    END
  END wd_in_B[56]
  PIN wd_in_A[57]
    DIRECTION INPUT ;
    USE SIGNAL ;
    SHAPE ABUTMENT ;
    PORT
      LAYER M4 ;
      RECT 0.000 322.608 0.024 322.632 ;
    END
  END wd_in_A[57]
  PIN wd_in_B[57]
    DIRECTION INPUT ;
    USE SIGNAL ;
    SHAPE ABUTMENT ;
    PORT
      LAYER M4 ;
      RECT 103.336 322.608 103.360 322.632 ;
    END
  END wd_in_B[57]
  PIN wd_in_A[58]
    DIRECTION INPUT ;
    USE SIGNAL ;
    SHAPE ABUTMENT ;
    PORT
      LAYER M4 ;
      RECT 0.000 324.336 0.024 324.360 ;
    END
  END wd_in_A[58]
  PIN wd_in_B[58]
    DIRECTION INPUT ;
    USE SIGNAL ;
    SHAPE ABUTMENT ;
    PORT
      LAYER M4 ;
      RECT 103.336 324.336 103.360 324.360 ;
    END
  END wd_in_B[58]
  PIN wd_in_A[59]
    DIRECTION INPUT ;
    USE SIGNAL ;
    SHAPE ABUTMENT ;
    PORT
      LAYER M4 ;
      RECT 0.000 326.064 0.024 326.088 ;
    END
  END wd_in_A[59]
  PIN wd_in_B[59]
    DIRECTION INPUT ;
    USE SIGNAL ;
    SHAPE ABUTMENT ;
    PORT
      LAYER M4 ;
      RECT 103.336 326.064 103.360 326.088 ;
    END
  END wd_in_B[59]
  PIN wd_in_A[60]
    DIRECTION INPUT ;
    USE SIGNAL ;
    SHAPE ABUTMENT ;
    PORT
      LAYER M4 ;
      RECT 0.000 327.792 0.024 327.816 ;
    END
  END wd_in_A[60]
  PIN wd_in_B[60]
    DIRECTION INPUT ;
    USE SIGNAL ;
    SHAPE ABUTMENT ;
    PORT
      LAYER M4 ;
      RECT 103.336 327.792 103.360 327.816 ;
    END
  END wd_in_B[60]
  PIN wd_in_A[61]
    DIRECTION INPUT ;
    USE SIGNAL ;
    SHAPE ABUTMENT ;
    PORT
      LAYER M4 ;
      RECT 0.000 329.520 0.024 329.544 ;
    END
  END wd_in_A[61]
  PIN wd_in_B[61]
    DIRECTION INPUT ;
    USE SIGNAL ;
    SHAPE ABUTMENT ;
    PORT
      LAYER M4 ;
      RECT 103.336 329.520 103.360 329.544 ;
    END
  END wd_in_B[61]
  PIN wd_in_A[62]
    DIRECTION INPUT ;
    USE SIGNAL ;
    SHAPE ABUTMENT ;
    PORT
      LAYER M4 ;
      RECT 0.000 331.248 0.024 331.272 ;
    END
  END wd_in_A[62]
  PIN wd_in_B[62]
    DIRECTION INPUT ;
    USE SIGNAL ;
    SHAPE ABUTMENT ;
    PORT
      LAYER M4 ;
      RECT 103.336 331.248 103.360 331.272 ;
    END
  END wd_in_B[62]
  PIN wd_in_A[63]
    DIRECTION INPUT ;
    USE SIGNAL ;
    SHAPE ABUTMENT ;
    PORT
      LAYER M4 ;
      RECT 0.000 332.976 0.024 333.000 ;
    END
  END wd_in_A[63]
  PIN wd_in_B[63]
    DIRECTION INPUT ;
    USE SIGNAL ;
    SHAPE ABUTMENT ;
    PORT
      LAYER M4 ;
      RECT 103.336 332.976 103.360 333.000 ;
    END
  END wd_in_B[63]
  PIN addr_in_A[0]
    DIRECTION INPUT ;
    USE SIGNAL ;
    SHAPE ABUTMENT ;
    PORT
      LAYER M4 ;
      RECT 0.000 336.144 0.024 336.168 ;
    END
  END addr_in_A[0]
  PIN addr_in_B[0]
    DIRECTION INPUT ;
    USE SIGNAL ;
    SHAPE ABUTMENT ;
    PORT
      LAYER M4 ;
      RECT 103.336 336.144 103.360 336.168 ;
    END
  END addr_in_B[0]
  PIN addr_in_A[1]
    DIRECTION INPUT ;
    USE SIGNAL ;
    SHAPE ABUTMENT ;
    PORT
      LAYER M4 ;
      RECT 0.000 337.872 0.024 337.896 ;
    END
  END addr_in_A[1]
  PIN addr_in_B[1]
    DIRECTION INPUT ;
    USE SIGNAL ;
    SHAPE ABUTMENT ;
    PORT
      LAYER M4 ;
      RECT 103.336 337.872 103.360 337.896 ;
    END
  END addr_in_B[1]
  PIN addr_in_A[2]
    DIRECTION INPUT ;
    USE SIGNAL ;
    SHAPE ABUTMENT ;
    PORT
      LAYER M4 ;
      RECT 0.000 339.600 0.024 339.624 ;
    END
  END addr_in_A[2]
  PIN addr_in_B[2]
    DIRECTION INPUT ;
    USE SIGNAL ;
    SHAPE ABUTMENT ;
    PORT
      LAYER M4 ;
      RECT 103.336 339.600 103.360 339.624 ;
    END
  END addr_in_B[2]
  PIN addr_in_A[3]
    DIRECTION INPUT ;
    USE SIGNAL ;
    SHAPE ABUTMENT ;
    PORT
      LAYER M4 ;
      RECT 0.000 341.328 0.024 341.352 ;
    END
  END addr_in_A[3]
  PIN addr_in_B[3]
    DIRECTION INPUT ;
    USE SIGNAL ;
    SHAPE ABUTMENT ;
    PORT
      LAYER M4 ;
      RECT 103.336 341.328 103.360 341.352 ;
    END
  END addr_in_B[3]
  PIN addr_in_A[4]
    DIRECTION INPUT ;
    USE SIGNAL ;
    SHAPE ABUTMENT ;
    PORT
      LAYER M4 ;
      RECT 0.000 343.056 0.024 343.080 ;
    END
  END addr_in_A[4]
  PIN addr_in_B[4]
    DIRECTION INPUT ;
    USE SIGNAL ;
    SHAPE ABUTMENT ;
    PORT
      LAYER M4 ;
      RECT 103.336 343.056 103.360 343.080 ;
    END
  END addr_in_B[4]
  PIN addr_in_A[5]
    DIRECTION INPUT ;
    USE SIGNAL ;
    SHAPE ABUTMENT ;
    PORT
      LAYER M4 ;
      RECT 0.000 344.784 0.024 344.808 ;
    END
  END addr_in_A[5]
  PIN addr_in_B[5]
    DIRECTION INPUT ;
    USE SIGNAL ;
    SHAPE ABUTMENT ;
    PORT
      LAYER M4 ;
      RECT 103.336 344.784 103.360 344.808 ;
    END
  END addr_in_B[5]
  PIN addr_in_A[6]
    DIRECTION INPUT ;
    USE SIGNAL ;
    SHAPE ABUTMENT ;
    PORT
      LAYER M4 ;
      RECT 0.000 346.512 0.024 346.536 ;
    END
  END addr_in_A[6]
  PIN addr_in_B[6]
    DIRECTION INPUT ;
    USE SIGNAL ;
    SHAPE ABUTMENT ;
    PORT
      LAYER M4 ;
      RECT 103.336 346.512 103.360 346.536 ;
    END
  END addr_in_B[6]
  PIN addr_in_A[7]
    DIRECTION INPUT ;
    USE SIGNAL ;
    SHAPE ABUTMENT ;
    PORT
      LAYER M4 ;
      RECT 0.000 348.240 0.024 348.264 ;
    END
  END addr_in_A[7]
  PIN addr_in_B[7]
    DIRECTION INPUT ;
    USE SIGNAL ;
    SHAPE ABUTMENT ;
    PORT
      LAYER M4 ;
      RECT 103.336 348.240 103.360 348.264 ;
    END
  END addr_in_B[7]
  PIN addr_in_A[8]
    DIRECTION INPUT ;
    USE SIGNAL ;
    SHAPE ABUTMENT ;
    PORT
      LAYER M4 ;
      RECT 0.000 349.968 0.024 349.992 ;
    END
  END addr_in_A[8]
  PIN addr_in_B[8]
    DIRECTION INPUT ;
    USE SIGNAL ;
    SHAPE ABUTMENT ;
    PORT
      LAYER M4 ;
      RECT 103.336 349.968 103.360 349.992 ;
    END
  END addr_in_B[8]
  PIN addr_in_A[9]
    DIRECTION INPUT ;
    USE SIGNAL ;
    SHAPE ABUTMENT ;
    PORT
      LAYER M4 ;
      RECT 0.000 351.696 0.024 351.720 ;
    END
  END addr_in_A[9]
  PIN addr_in_B[9]
    DIRECTION INPUT ;
    USE SIGNAL ;
    SHAPE ABUTMENT ;
    PORT
      LAYER M4 ;
      RECT 103.336 351.696 103.360 351.720 ;
    END
  END addr_in_B[9]
  PIN addr_in_A[10]
    DIRECTION INPUT ;
    USE SIGNAL ;
    SHAPE ABUTMENT ;
    PORT
      LAYER M4 ;
      RECT 0.000 353.424 0.024 353.448 ;
    END
  END addr_in_A[10]
  PIN addr_in_B[10]
    DIRECTION INPUT ;
    USE SIGNAL ;
    SHAPE ABUTMENT ;
    PORT
      LAYER M4 ;
      RECT 103.336 353.424 103.360 353.448 ;
    END
  END addr_in_B[10]
  PIN addr_in_A[11]
    DIRECTION INPUT ;
    USE SIGNAL ;
    SHAPE ABUTMENT ;
    PORT
      LAYER M4 ;
      RECT 0.000 355.152 0.024 355.176 ;
    END
  END addr_in_A[11]
  PIN addr_in_B[11]
    DIRECTION INPUT ;
    USE SIGNAL ;
    SHAPE ABUTMENT ;
    PORT
      LAYER M4 ;
      RECT 103.336 355.152 103.360 355.176 ;
    END
  END addr_in_B[11]
  PIN addr_in_A[12]
    DIRECTION INPUT ;
    USE SIGNAL ;
    SHAPE ABUTMENT ;
    PORT
      LAYER M4 ;
      RECT 0.000 356.880 0.024 356.904 ;
    END
  END addr_in_A[12]
  PIN addr_in_B[12]
    DIRECTION INPUT ;
    USE SIGNAL ;
    SHAPE ABUTMENT ;
    PORT
      LAYER M4 ;
      RECT 103.336 356.880 103.360 356.904 ;
    END
  END addr_in_B[12]
  PIN we_in_A
    DIRECTION INPUT ;
    USE SIGNAL ;
    SHAPE ABUTMENT ;
    PORT
      LAYER M4 ;
      RECT 0.000 360.048 0.024 360.072 ;
    END
  END we_in_A
  PIN we_in_B
    DIRECTION INPUT ;
    USE SIGNAL ;
    SHAPE ABUTMENT ;
    PORT
      LAYER M4 ;
      RECT 103.336 360.048 103.360 360.072 ;
    END
  END we_in_B
  PIN ce_in_A
    DIRECTION INPUT ;
    USE SIGNAL ;
    SHAPE ABUTMENT ;
    PORT
      LAYER M4 ;
      RECT 0.000 361.776 0.024 361.800 ;
    END
  END ce_in_A
  PIN clk_A
    DIRECTION INPUT ;
    USE SIGNAL ;
    SHAPE ABUTMENT ;
    PORT
      LAYER M4 ;
      RECT 0.000 363.504 0.024 363.528 ;
    END
  END clk_A
  PIN ce_in_B
    DIRECTION INPUT ;
    USE SIGNAL ;
    SHAPE ABUTMENT ;
    PORT
      LAYER M4 ;
      RECT 0.000 365.232 0.024 365.256 ;
    END
  END ce_in_B
  PIN clk_B
    DIRECTION INPUT ;
    USE SIGNAL ;
    SHAPE ABUTMENT ;
    PORT
      LAYER M4 ;
      RECT 0.000 366.960 0.024 366.984 ;
    END
  END clk_B
  PIN VSS
    DIRECTION INOUT ;
    USE GROUND ;
    PORT
      LAYER M4 ;
      RECT 0.048 0.000 103.312 0.096 ;
      RECT 0.048 0.768 103.312 0.864 ;
      RECT 0.048 1.536 103.312 1.632 ;
      RECT 0.048 2.304 103.312 2.400 ;
      RECT 0.048 3.072 103.312 3.168 ;
      RECT 0.048 3.840 103.312 3.936 ;
      RECT 0.048 4.608 103.312 4.704 ;
      RECT 0.048 5.376 103.312 5.472 ;
      RECT 0.048 6.144 103.312 6.240 ;
      RECT 0.048 6.912 103.312 7.008 ;
      RECT 0.048 7.680 103.312 7.776 ;
      RECT 0.048 8.448 103.312 8.544 ;
      RECT 0.048 9.216 103.312 9.312 ;
      RECT 0.048 9.984 103.312 10.080 ;
      RECT 0.048 10.752 103.312 10.848 ;
      RECT 0.048 11.520 103.312 11.616 ;
      RECT 0.048 12.288 103.312 12.384 ;
      RECT 0.048 13.056 103.312 13.152 ;
      RECT 0.048 13.824 103.312 13.920 ;
      RECT 0.048 14.592 103.312 14.688 ;
      RECT 0.048 15.360 103.312 15.456 ;
      RECT 0.048 16.128 103.312 16.224 ;
      RECT 0.048 16.896 103.312 16.992 ;
      RECT 0.048 17.664 103.312 17.760 ;
      RECT 0.048 18.432 103.312 18.528 ;
      RECT 0.048 19.200 103.312 19.296 ;
      RECT 0.048 19.968 103.312 20.064 ;
      RECT 0.048 20.736 103.312 20.832 ;
      RECT 0.048 21.504 103.312 21.600 ;
      RECT 0.048 22.272 103.312 22.368 ;
      RECT 0.048 23.040 103.312 23.136 ;
      RECT 0.048 23.808 103.312 23.904 ;
      RECT 0.048 24.576 103.312 24.672 ;
      RECT 0.048 25.344 103.312 25.440 ;
      RECT 0.048 26.112 103.312 26.208 ;
      RECT 0.048 26.880 103.312 26.976 ;
      RECT 0.048 27.648 103.312 27.744 ;
      RECT 0.048 28.416 103.312 28.512 ;
      RECT 0.048 29.184 103.312 29.280 ;
      RECT 0.048 29.952 103.312 30.048 ;
      RECT 0.048 30.720 103.312 30.816 ;
      RECT 0.048 31.488 103.312 31.584 ;
      RECT 0.048 32.256 103.312 32.352 ;
      RECT 0.048 33.024 103.312 33.120 ;
      RECT 0.048 33.792 103.312 33.888 ;
      RECT 0.048 34.560 103.312 34.656 ;
      RECT 0.048 35.328 103.312 35.424 ;
      RECT 0.048 36.096 103.312 36.192 ;
      RECT 0.048 36.864 103.312 36.960 ;
      RECT 0.048 37.632 103.312 37.728 ;
      RECT 0.048 38.400 103.312 38.496 ;
      RECT 0.048 39.168 103.312 39.264 ;
      RECT 0.048 39.936 103.312 40.032 ;
      RECT 0.048 40.704 103.312 40.800 ;
      RECT 0.048 41.472 103.312 41.568 ;
      RECT 0.048 42.240 103.312 42.336 ;
      RECT 0.048 43.008 103.312 43.104 ;
      RECT 0.048 43.776 103.312 43.872 ;
      RECT 0.048 44.544 103.312 44.640 ;
      RECT 0.048 45.312 103.312 45.408 ;
      RECT 0.048 46.080 103.312 46.176 ;
      RECT 0.048 46.848 103.312 46.944 ;
      RECT 0.048 47.616 103.312 47.712 ;
      RECT 0.048 48.384 103.312 48.480 ;
      RECT 0.048 49.152 103.312 49.248 ;
      RECT 0.048 49.920 103.312 50.016 ;
      RECT 0.048 50.688 103.312 50.784 ;
      RECT 0.048 51.456 103.312 51.552 ;
      RECT 0.048 52.224 103.312 52.320 ;
      RECT 0.048 52.992 103.312 53.088 ;
      RECT 0.048 53.760 103.312 53.856 ;
      RECT 0.048 54.528 103.312 54.624 ;
      RECT 0.048 55.296 103.312 55.392 ;
      RECT 0.048 56.064 103.312 56.160 ;
      RECT 0.048 56.832 103.312 56.928 ;
      RECT 0.048 57.600 103.312 57.696 ;
      RECT 0.048 58.368 103.312 58.464 ;
      RECT 0.048 59.136 103.312 59.232 ;
      RECT 0.048 59.904 103.312 60.000 ;
      RECT 0.048 60.672 103.312 60.768 ;
      RECT 0.048 61.440 103.312 61.536 ;
      RECT 0.048 62.208 103.312 62.304 ;
      RECT 0.048 62.976 103.312 63.072 ;
      RECT 0.048 63.744 103.312 63.840 ;
      RECT 0.048 64.512 103.312 64.608 ;
      RECT 0.048 65.280 103.312 65.376 ;
      RECT 0.048 66.048 103.312 66.144 ;
      RECT 0.048 66.816 103.312 66.912 ;
      RECT 0.048 67.584 103.312 67.680 ;
      RECT 0.048 68.352 103.312 68.448 ;
      RECT 0.048 69.120 103.312 69.216 ;
      RECT 0.048 69.888 103.312 69.984 ;
      RECT 0.048 70.656 103.312 70.752 ;
      RECT 0.048 71.424 103.312 71.520 ;
      RECT 0.048 72.192 103.312 72.288 ;
      RECT 0.048 72.960 103.312 73.056 ;
      RECT 0.048 73.728 103.312 73.824 ;
      RECT 0.048 74.496 103.312 74.592 ;
      RECT 0.048 75.264 103.312 75.360 ;
      RECT 0.048 76.032 103.312 76.128 ;
      RECT 0.048 76.800 103.312 76.896 ;
      RECT 0.048 77.568 103.312 77.664 ;
      RECT 0.048 78.336 103.312 78.432 ;
      RECT 0.048 79.104 103.312 79.200 ;
      RECT 0.048 79.872 103.312 79.968 ;
      RECT 0.048 80.640 103.312 80.736 ;
      RECT 0.048 81.408 103.312 81.504 ;
      RECT 0.048 82.176 103.312 82.272 ;
      RECT 0.048 82.944 103.312 83.040 ;
      RECT 0.048 83.712 103.312 83.808 ;
      RECT 0.048 84.480 103.312 84.576 ;
      RECT 0.048 85.248 103.312 85.344 ;
      RECT 0.048 86.016 103.312 86.112 ;
      RECT 0.048 86.784 103.312 86.880 ;
      RECT 0.048 87.552 103.312 87.648 ;
      RECT 0.048 88.320 103.312 88.416 ;
      RECT 0.048 89.088 103.312 89.184 ;
      RECT 0.048 89.856 103.312 89.952 ;
      RECT 0.048 90.624 103.312 90.720 ;
      RECT 0.048 91.392 103.312 91.488 ;
      RECT 0.048 92.160 103.312 92.256 ;
      RECT 0.048 92.928 103.312 93.024 ;
      RECT 0.048 93.696 103.312 93.792 ;
      RECT 0.048 94.464 103.312 94.560 ;
      RECT 0.048 95.232 103.312 95.328 ;
      RECT 0.048 96.000 103.312 96.096 ;
      RECT 0.048 96.768 103.312 96.864 ;
      RECT 0.048 97.536 103.312 97.632 ;
      RECT 0.048 98.304 103.312 98.400 ;
      RECT 0.048 99.072 103.312 99.168 ;
      RECT 0.048 99.840 103.312 99.936 ;
      RECT 0.048 100.608 103.312 100.704 ;
      RECT 0.048 101.376 103.312 101.472 ;
      RECT 0.048 102.144 103.312 102.240 ;
      RECT 0.048 102.912 103.312 103.008 ;
      RECT 0.048 103.680 103.312 103.776 ;
      RECT 0.048 104.448 103.312 104.544 ;
      RECT 0.048 105.216 103.312 105.312 ;
      RECT 0.048 105.984 103.312 106.080 ;
      RECT 0.048 106.752 103.312 106.848 ;
      RECT 0.048 107.520 103.312 107.616 ;
      RECT 0.048 108.288 103.312 108.384 ;
      RECT 0.048 109.056 103.312 109.152 ;
      RECT 0.048 109.824 103.312 109.920 ;
      RECT 0.048 110.592 103.312 110.688 ;
      RECT 0.048 111.360 103.312 111.456 ;
      RECT 0.048 112.128 103.312 112.224 ;
      RECT 0.048 112.896 103.312 112.992 ;
      RECT 0.048 113.664 103.312 113.760 ;
      RECT 0.048 114.432 103.312 114.528 ;
      RECT 0.048 115.200 103.312 115.296 ;
      RECT 0.048 115.968 103.312 116.064 ;
      RECT 0.048 116.736 103.312 116.832 ;
      RECT 0.048 117.504 103.312 117.600 ;
      RECT 0.048 118.272 103.312 118.368 ;
      RECT 0.048 119.040 103.312 119.136 ;
      RECT 0.048 119.808 103.312 119.904 ;
      RECT 0.048 120.576 103.312 120.672 ;
      RECT 0.048 121.344 103.312 121.440 ;
      RECT 0.048 122.112 103.312 122.208 ;
      RECT 0.048 122.880 103.312 122.976 ;
      RECT 0.048 123.648 103.312 123.744 ;
      RECT 0.048 124.416 103.312 124.512 ;
      RECT 0.048 125.184 103.312 125.280 ;
      RECT 0.048 125.952 103.312 126.048 ;
      RECT 0.048 126.720 103.312 126.816 ;
      RECT 0.048 127.488 103.312 127.584 ;
      RECT 0.048 128.256 103.312 128.352 ;
      RECT 0.048 129.024 103.312 129.120 ;
      RECT 0.048 129.792 103.312 129.888 ;
      RECT 0.048 130.560 103.312 130.656 ;
      RECT 0.048 131.328 103.312 131.424 ;
      RECT 0.048 132.096 103.312 132.192 ;
      RECT 0.048 132.864 103.312 132.960 ;
      RECT 0.048 133.632 103.312 133.728 ;
      RECT 0.048 134.400 103.312 134.496 ;
      RECT 0.048 135.168 103.312 135.264 ;
      RECT 0.048 135.936 103.312 136.032 ;
      RECT 0.048 136.704 103.312 136.800 ;
      RECT 0.048 137.472 103.312 137.568 ;
      RECT 0.048 138.240 103.312 138.336 ;
      RECT 0.048 139.008 103.312 139.104 ;
      RECT 0.048 139.776 103.312 139.872 ;
      RECT 0.048 140.544 103.312 140.640 ;
      RECT 0.048 141.312 103.312 141.408 ;
      RECT 0.048 142.080 103.312 142.176 ;
      RECT 0.048 142.848 103.312 142.944 ;
      RECT 0.048 143.616 103.312 143.712 ;
      RECT 0.048 144.384 103.312 144.480 ;
      RECT 0.048 145.152 103.312 145.248 ;
      RECT 0.048 145.920 103.312 146.016 ;
      RECT 0.048 146.688 103.312 146.784 ;
      RECT 0.048 147.456 103.312 147.552 ;
      RECT 0.048 148.224 103.312 148.320 ;
      RECT 0.048 148.992 103.312 149.088 ;
      RECT 0.048 149.760 103.312 149.856 ;
      RECT 0.048 150.528 103.312 150.624 ;
      RECT 0.048 151.296 103.312 151.392 ;
      RECT 0.048 152.064 103.312 152.160 ;
      RECT 0.048 152.832 103.312 152.928 ;
      RECT 0.048 153.600 103.312 153.696 ;
      RECT 0.048 154.368 103.312 154.464 ;
      RECT 0.048 155.136 103.312 155.232 ;
      RECT 0.048 155.904 103.312 156.000 ;
      RECT 0.048 156.672 103.312 156.768 ;
      RECT 0.048 157.440 103.312 157.536 ;
      RECT 0.048 158.208 103.312 158.304 ;
      RECT 0.048 158.976 103.312 159.072 ;
      RECT 0.048 159.744 103.312 159.840 ;
      RECT 0.048 160.512 103.312 160.608 ;
      RECT 0.048 161.280 103.312 161.376 ;
      RECT 0.048 162.048 103.312 162.144 ;
      RECT 0.048 162.816 103.312 162.912 ;
      RECT 0.048 163.584 103.312 163.680 ;
      RECT 0.048 164.352 103.312 164.448 ;
      RECT 0.048 165.120 103.312 165.216 ;
      RECT 0.048 165.888 103.312 165.984 ;
      RECT 0.048 166.656 103.312 166.752 ;
      RECT 0.048 167.424 103.312 167.520 ;
      RECT 0.048 168.192 103.312 168.288 ;
      RECT 0.048 168.960 103.312 169.056 ;
      RECT 0.048 169.728 103.312 169.824 ;
      RECT 0.048 170.496 103.312 170.592 ;
      RECT 0.048 171.264 103.312 171.360 ;
      RECT 0.048 172.032 103.312 172.128 ;
      RECT 0.048 172.800 103.312 172.896 ;
      RECT 0.048 173.568 103.312 173.664 ;
      RECT 0.048 174.336 103.312 174.432 ;
      RECT 0.048 175.104 103.312 175.200 ;
      RECT 0.048 175.872 103.312 175.968 ;
      RECT 0.048 176.640 103.312 176.736 ;
      RECT 0.048 177.408 103.312 177.504 ;
      RECT 0.048 178.176 103.312 178.272 ;
      RECT 0.048 178.944 103.312 179.040 ;
      RECT 0.048 179.712 103.312 179.808 ;
      RECT 0.048 180.480 103.312 180.576 ;
      RECT 0.048 181.248 103.312 181.344 ;
      RECT 0.048 182.016 103.312 182.112 ;
      RECT 0.048 182.784 103.312 182.880 ;
      RECT 0.048 183.552 103.312 183.648 ;
      RECT 0.048 184.320 103.312 184.416 ;
      RECT 0.048 185.088 103.312 185.184 ;
      RECT 0.048 185.856 103.312 185.952 ;
      RECT 0.048 186.624 103.312 186.720 ;
      RECT 0.048 187.392 103.312 187.488 ;
      RECT 0.048 188.160 103.312 188.256 ;
      RECT 0.048 188.928 103.312 189.024 ;
      RECT 0.048 189.696 103.312 189.792 ;
      RECT 0.048 190.464 103.312 190.560 ;
      RECT 0.048 191.232 103.312 191.328 ;
      RECT 0.048 192.000 103.312 192.096 ;
      RECT 0.048 192.768 103.312 192.864 ;
      RECT 0.048 193.536 103.312 193.632 ;
      RECT 0.048 194.304 103.312 194.400 ;
      RECT 0.048 195.072 103.312 195.168 ;
      RECT 0.048 195.840 103.312 195.936 ;
      RECT 0.048 196.608 103.312 196.704 ;
      RECT 0.048 197.376 103.312 197.472 ;
      RECT 0.048 198.144 103.312 198.240 ;
      RECT 0.048 198.912 103.312 199.008 ;
      RECT 0.048 199.680 103.312 199.776 ;
      RECT 0.048 200.448 103.312 200.544 ;
      RECT 0.048 201.216 103.312 201.312 ;
      RECT 0.048 201.984 103.312 202.080 ;
      RECT 0.048 202.752 103.312 202.848 ;
      RECT 0.048 203.520 103.312 203.616 ;
      RECT 0.048 204.288 103.312 204.384 ;
      RECT 0.048 205.056 103.312 205.152 ;
      RECT 0.048 205.824 103.312 205.920 ;
      RECT 0.048 206.592 103.312 206.688 ;
      RECT 0.048 207.360 103.312 207.456 ;
      RECT 0.048 208.128 103.312 208.224 ;
      RECT 0.048 208.896 103.312 208.992 ;
      RECT 0.048 209.664 103.312 209.760 ;
      RECT 0.048 210.432 103.312 210.528 ;
      RECT 0.048 211.200 103.312 211.296 ;
      RECT 0.048 211.968 103.312 212.064 ;
      RECT 0.048 212.736 103.312 212.832 ;
      RECT 0.048 213.504 103.312 213.600 ;
      RECT 0.048 214.272 103.312 214.368 ;
      RECT 0.048 215.040 103.312 215.136 ;
      RECT 0.048 215.808 103.312 215.904 ;
      RECT 0.048 216.576 103.312 216.672 ;
      RECT 0.048 217.344 103.312 217.440 ;
      RECT 0.048 218.112 103.312 218.208 ;
      RECT 0.048 218.880 103.312 218.976 ;
      RECT 0.048 219.648 103.312 219.744 ;
      RECT 0.048 220.416 103.312 220.512 ;
      RECT 0.048 221.184 103.312 221.280 ;
      RECT 0.048 221.952 103.312 222.048 ;
      RECT 0.048 222.720 103.312 222.816 ;
      RECT 0.048 223.488 103.312 223.584 ;
      RECT 0.048 224.256 103.312 224.352 ;
      RECT 0.048 225.024 103.312 225.120 ;
      RECT 0.048 225.792 103.312 225.888 ;
      RECT 0.048 226.560 103.312 226.656 ;
      RECT 0.048 227.328 103.312 227.424 ;
      RECT 0.048 228.096 103.312 228.192 ;
      RECT 0.048 228.864 103.312 228.960 ;
      RECT 0.048 229.632 103.312 229.728 ;
      RECT 0.048 230.400 103.312 230.496 ;
      RECT 0.048 231.168 103.312 231.264 ;
      RECT 0.048 231.936 103.312 232.032 ;
      RECT 0.048 232.704 103.312 232.800 ;
      RECT 0.048 233.472 103.312 233.568 ;
      RECT 0.048 234.240 103.312 234.336 ;
      RECT 0.048 235.008 103.312 235.104 ;
      RECT 0.048 235.776 103.312 235.872 ;
      RECT 0.048 236.544 103.312 236.640 ;
      RECT 0.048 237.312 103.312 237.408 ;
      RECT 0.048 238.080 103.312 238.176 ;
      RECT 0.048 238.848 103.312 238.944 ;
      RECT 0.048 239.616 103.312 239.712 ;
      RECT 0.048 240.384 103.312 240.480 ;
      RECT 0.048 241.152 103.312 241.248 ;
      RECT 0.048 241.920 103.312 242.016 ;
      RECT 0.048 242.688 103.312 242.784 ;
      RECT 0.048 243.456 103.312 243.552 ;
      RECT 0.048 244.224 103.312 244.320 ;
      RECT 0.048 244.992 103.312 245.088 ;
      RECT 0.048 245.760 103.312 245.856 ;
      RECT 0.048 246.528 103.312 246.624 ;
      RECT 0.048 247.296 103.312 247.392 ;
      RECT 0.048 248.064 103.312 248.160 ;
      RECT 0.048 248.832 103.312 248.928 ;
      RECT 0.048 249.600 103.312 249.696 ;
      RECT 0.048 250.368 103.312 250.464 ;
      RECT 0.048 251.136 103.312 251.232 ;
      RECT 0.048 251.904 103.312 252.000 ;
      RECT 0.048 252.672 103.312 252.768 ;
      RECT 0.048 253.440 103.312 253.536 ;
      RECT 0.048 254.208 103.312 254.304 ;
      RECT 0.048 254.976 103.312 255.072 ;
      RECT 0.048 255.744 103.312 255.840 ;
      RECT 0.048 256.512 103.312 256.608 ;
      RECT 0.048 257.280 103.312 257.376 ;
      RECT 0.048 258.048 103.312 258.144 ;
      RECT 0.048 258.816 103.312 258.912 ;
      RECT 0.048 259.584 103.312 259.680 ;
      RECT 0.048 260.352 103.312 260.448 ;
      RECT 0.048 261.120 103.312 261.216 ;
      RECT 0.048 261.888 103.312 261.984 ;
      RECT 0.048 262.656 103.312 262.752 ;
      RECT 0.048 263.424 103.312 263.520 ;
      RECT 0.048 264.192 103.312 264.288 ;
      RECT 0.048 264.960 103.312 265.056 ;
      RECT 0.048 265.728 103.312 265.824 ;
      RECT 0.048 266.496 103.312 266.592 ;
      RECT 0.048 267.264 103.312 267.360 ;
      RECT 0.048 268.032 103.312 268.128 ;
      RECT 0.048 268.800 103.312 268.896 ;
      RECT 0.048 269.568 103.312 269.664 ;
      RECT 0.048 270.336 103.312 270.432 ;
      RECT 0.048 271.104 103.312 271.200 ;
      RECT 0.048 271.872 103.312 271.968 ;
      RECT 0.048 272.640 103.312 272.736 ;
      RECT 0.048 273.408 103.312 273.504 ;
      RECT 0.048 274.176 103.312 274.272 ;
      RECT 0.048 274.944 103.312 275.040 ;
      RECT 0.048 275.712 103.312 275.808 ;
      RECT 0.048 276.480 103.312 276.576 ;
      RECT 0.048 277.248 103.312 277.344 ;
      RECT 0.048 278.016 103.312 278.112 ;
      RECT 0.048 278.784 103.312 278.880 ;
      RECT 0.048 279.552 103.312 279.648 ;
      RECT 0.048 280.320 103.312 280.416 ;
      RECT 0.048 281.088 103.312 281.184 ;
      RECT 0.048 281.856 103.312 281.952 ;
      RECT 0.048 282.624 103.312 282.720 ;
      RECT 0.048 283.392 103.312 283.488 ;
      RECT 0.048 284.160 103.312 284.256 ;
      RECT 0.048 284.928 103.312 285.024 ;
      RECT 0.048 285.696 103.312 285.792 ;
      RECT 0.048 286.464 103.312 286.560 ;
      RECT 0.048 287.232 103.312 287.328 ;
      RECT 0.048 288.000 103.312 288.096 ;
      RECT 0.048 288.768 103.312 288.864 ;
      RECT 0.048 289.536 103.312 289.632 ;
      RECT 0.048 290.304 103.312 290.400 ;
      RECT 0.048 291.072 103.312 291.168 ;
      RECT 0.048 291.840 103.312 291.936 ;
      RECT 0.048 292.608 103.312 292.704 ;
      RECT 0.048 293.376 103.312 293.472 ;
      RECT 0.048 294.144 103.312 294.240 ;
      RECT 0.048 294.912 103.312 295.008 ;
      RECT 0.048 295.680 103.312 295.776 ;
      RECT 0.048 296.448 103.312 296.544 ;
      RECT 0.048 297.216 103.312 297.312 ;
      RECT 0.048 297.984 103.312 298.080 ;
      RECT 0.048 298.752 103.312 298.848 ;
      RECT 0.048 299.520 103.312 299.616 ;
      RECT 0.048 300.288 103.312 300.384 ;
      RECT 0.048 301.056 103.312 301.152 ;
      RECT 0.048 301.824 103.312 301.920 ;
      RECT 0.048 302.592 103.312 302.688 ;
      RECT 0.048 303.360 103.312 303.456 ;
      RECT 0.048 304.128 103.312 304.224 ;
      RECT 0.048 304.896 103.312 304.992 ;
      RECT 0.048 305.664 103.312 305.760 ;
      RECT 0.048 306.432 103.312 306.528 ;
      RECT 0.048 307.200 103.312 307.296 ;
      RECT 0.048 307.968 103.312 308.064 ;
      RECT 0.048 308.736 103.312 308.832 ;
      RECT 0.048 309.504 103.312 309.600 ;
      RECT 0.048 310.272 103.312 310.368 ;
      RECT 0.048 311.040 103.312 311.136 ;
      RECT 0.048 311.808 103.312 311.904 ;
      RECT 0.048 312.576 103.312 312.672 ;
      RECT 0.048 313.344 103.312 313.440 ;
      RECT 0.048 314.112 103.312 314.208 ;
      RECT 0.048 314.880 103.312 314.976 ;
      RECT 0.048 315.648 103.312 315.744 ;
      RECT 0.048 316.416 103.312 316.512 ;
      RECT 0.048 317.184 103.312 317.280 ;
      RECT 0.048 317.952 103.312 318.048 ;
      RECT 0.048 318.720 103.312 318.816 ;
      RECT 0.048 319.488 103.312 319.584 ;
      RECT 0.048 320.256 103.312 320.352 ;
      RECT 0.048 321.024 103.312 321.120 ;
      RECT 0.048 321.792 103.312 321.888 ;
      RECT 0.048 322.560 103.312 322.656 ;
      RECT 0.048 323.328 103.312 323.424 ;
      RECT 0.048 324.096 103.312 324.192 ;
      RECT 0.048 324.864 103.312 324.960 ;
      RECT 0.048 325.632 103.312 325.728 ;
      RECT 0.048 326.400 103.312 326.496 ;
      RECT 0.048 327.168 103.312 327.264 ;
      RECT 0.048 327.936 103.312 328.032 ;
      RECT 0.048 328.704 103.312 328.800 ;
      RECT 0.048 329.472 103.312 329.568 ;
      RECT 0.048 330.240 103.312 330.336 ;
      RECT 0.048 331.008 103.312 331.104 ;
      RECT 0.048 331.776 103.312 331.872 ;
      RECT 0.048 332.544 103.312 332.640 ;
      RECT 0.048 333.312 103.312 333.408 ;
      RECT 0.048 334.080 103.312 334.176 ;
      RECT 0.048 334.848 103.312 334.944 ;
      RECT 0.048 335.616 103.312 335.712 ;
      RECT 0.048 336.384 103.312 336.480 ;
      RECT 0.048 337.152 103.312 337.248 ;
      RECT 0.048 337.920 103.312 338.016 ;
      RECT 0.048 338.688 103.312 338.784 ;
      RECT 0.048 339.456 103.312 339.552 ;
      RECT 0.048 340.224 103.312 340.320 ;
      RECT 0.048 340.992 103.312 341.088 ;
      RECT 0.048 341.760 103.312 341.856 ;
      RECT 0.048 342.528 103.312 342.624 ;
      RECT 0.048 343.296 103.312 343.392 ;
      RECT 0.048 344.064 103.312 344.160 ;
      RECT 0.048 344.832 103.312 344.928 ;
      RECT 0.048 345.600 103.312 345.696 ;
      RECT 0.048 346.368 103.312 346.464 ;
      RECT 0.048 347.136 103.312 347.232 ;
      RECT 0.048 347.904 103.312 348.000 ;
      RECT 0.048 348.672 103.312 348.768 ;
      RECT 0.048 349.440 103.312 349.536 ;
      RECT 0.048 350.208 103.312 350.304 ;
      RECT 0.048 350.976 103.312 351.072 ;
      RECT 0.048 351.744 103.312 351.840 ;
      RECT 0.048 352.512 103.312 352.608 ;
      RECT 0.048 353.280 103.312 353.376 ;
      RECT 0.048 354.048 103.312 354.144 ;
      RECT 0.048 354.816 103.312 354.912 ;
      RECT 0.048 355.584 103.312 355.680 ;
      RECT 0.048 356.352 103.312 356.448 ;
      RECT 0.048 357.120 103.312 357.216 ;
      RECT 0.048 357.888 103.312 357.984 ;
      RECT 0.048 358.656 103.312 358.752 ;
      RECT 0.048 359.424 103.312 359.520 ;
      RECT 0.048 360.192 103.312 360.288 ;
      RECT 0.048 360.960 103.312 361.056 ;
      RECT 0.048 361.728 103.312 361.824 ;
      RECT 0.048 362.496 103.312 362.592 ;
      RECT 0.048 363.264 103.312 363.360 ;
      RECT 0.048 364.032 103.312 364.128 ;
      RECT 0.048 364.800 103.312 364.896 ;
    END
  END VSS
  PIN VDD
    DIRECTION INOUT ;
    USE POWER ;
    PORT
      LAYER M4 ;
      RECT 0.048 0.384 103.312 0.480 ;
      RECT 0.048 1.152 103.312 1.248 ;
      RECT 0.048 1.920 103.312 2.016 ;
      RECT 0.048 2.688 103.312 2.784 ;
      RECT 0.048 3.456 103.312 3.552 ;
      RECT 0.048 4.224 103.312 4.320 ;
      RECT 0.048 4.992 103.312 5.088 ;
      RECT 0.048 5.760 103.312 5.856 ;
      RECT 0.048 6.528 103.312 6.624 ;
      RECT 0.048 7.296 103.312 7.392 ;
      RECT 0.048 8.064 103.312 8.160 ;
      RECT 0.048 8.832 103.312 8.928 ;
      RECT 0.048 9.600 103.312 9.696 ;
      RECT 0.048 10.368 103.312 10.464 ;
      RECT 0.048 11.136 103.312 11.232 ;
      RECT 0.048 11.904 103.312 12.000 ;
      RECT 0.048 12.672 103.312 12.768 ;
      RECT 0.048 13.440 103.312 13.536 ;
      RECT 0.048 14.208 103.312 14.304 ;
      RECT 0.048 14.976 103.312 15.072 ;
      RECT 0.048 15.744 103.312 15.840 ;
      RECT 0.048 16.512 103.312 16.608 ;
      RECT 0.048 17.280 103.312 17.376 ;
      RECT 0.048 18.048 103.312 18.144 ;
      RECT 0.048 18.816 103.312 18.912 ;
      RECT 0.048 19.584 103.312 19.680 ;
      RECT 0.048 20.352 103.312 20.448 ;
      RECT 0.048 21.120 103.312 21.216 ;
      RECT 0.048 21.888 103.312 21.984 ;
      RECT 0.048 22.656 103.312 22.752 ;
      RECT 0.048 23.424 103.312 23.520 ;
      RECT 0.048 24.192 103.312 24.288 ;
      RECT 0.048 24.960 103.312 25.056 ;
      RECT 0.048 25.728 103.312 25.824 ;
      RECT 0.048 26.496 103.312 26.592 ;
      RECT 0.048 27.264 103.312 27.360 ;
      RECT 0.048 28.032 103.312 28.128 ;
      RECT 0.048 28.800 103.312 28.896 ;
      RECT 0.048 29.568 103.312 29.664 ;
      RECT 0.048 30.336 103.312 30.432 ;
      RECT 0.048 31.104 103.312 31.200 ;
      RECT 0.048 31.872 103.312 31.968 ;
      RECT 0.048 32.640 103.312 32.736 ;
      RECT 0.048 33.408 103.312 33.504 ;
      RECT 0.048 34.176 103.312 34.272 ;
      RECT 0.048 34.944 103.312 35.040 ;
      RECT 0.048 35.712 103.312 35.808 ;
      RECT 0.048 36.480 103.312 36.576 ;
      RECT 0.048 37.248 103.312 37.344 ;
      RECT 0.048 38.016 103.312 38.112 ;
      RECT 0.048 38.784 103.312 38.880 ;
      RECT 0.048 39.552 103.312 39.648 ;
      RECT 0.048 40.320 103.312 40.416 ;
      RECT 0.048 41.088 103.312 41.184 ;
      RECT 0.048 41.856 103.312 41.952 ;
      RECT 0.048 42.624 103.312 42.720 ;
      RECT 0.048 43.392 103.312 43.488 ;
      RECT 0.048 44.160 103.312 44.256 ;
      RECT 0.048 44.928 103.312 45.024 ;
      RECT 0.048 45.696 103.312 45.792 ;
      RECT 0.048 46.464 103.312 46.560 ;
      RECT 0.048 47.232 103.312 47.328 ;
      RECT 0.048 48.000 103.312 48.096 ;
      RECT 0.048 48.768 103.312 48.864 ;
      RECT 0.048 49.536 103.312 49.632 ;
      RECT 0.048 50.304 103.312 50.400 ;
      RECT 0.048 51.072 103.312 51.168 ;
      RECT 0.048 51.840 103.312 51.936 ;
      RECT 0.048 52.608 103.312 52.704 ;
      RECT 0.048 53.376 103.312 53.472 ;
      RECT 0.048 54.144 103.312 54.240 ;
      RECT 0.048 54.912 103.312 55.008 ;
      RECT 0.048 55.680 103.312 55.776 ;
      RECT 0.048 56.448 103.312 56.544 ;
      RECT 0.048 57.216 103.312 57.312 ;
      RECT 0.048 57.984 103.312 58.080 ;
      RECT 0.048 58.752 103.312 58.848 ;
      RECT 0.048 59.520 103.312 59.616 ;
      RECT 0.048 60.288 103.312 60.384 ;
      RECT 0.048 61.056 103.312 61.152 ;
      RECT 0.048 61.824 103.312 61.920 ;
      RECT 0.048 62.592 103.312 62.688 ;
      RECT 0.048 63.360 103.312 63.456 ;
      RECT 0.048 64.128 103.312 64.224 ;
      RECT 0.048 64.896 103.312 64.992 ;
      RECT 0.048 65.664 103.312 65.760 ;
      RECT 0.048 66.432 103.312 66.528 ;
      RECT 0.048 67.200 103.312 67.296 ;
      RECT 0.048 67.968 103.312 68.064 ;
      RECT 0.048 68.736 103.312 68.832 ;
      RECT 0.048 69.504 103.312 69.600 ;
      RECT 0.048 70.272 103.312 70.368 ;
      RECT 0.048 71.040 103.312 71.136 ;
      RECT 0.048 71.808 103.312 71.904 ;
      RECT 0.048 72.576 103.312 72.672 ;
      RECT 0.048 73.344 103.312 73.440 ;
      RECT 0.048 74.112 103.312 74.208 ;
      RECT 0.048 74.880 103.312 74.976 ;
      RECT 0.048 75.648 103.312 75.744 ;
      RECT 0.048 76.416 103.312 76.512 ;
      RECT 0.048 77.184 103.312 77.280 ;
      RECT 0.048 77.952 103.312 78.048 ;
      RECT 0.048 78.720 103.312 78.816 ;
      RECT 0.048 79.488 103.312 79.584 ;
      RECT 0.048 80.256 103.312 80.352 ;
      RECT 0.048 81.024 103.312 81.120 ;
      RECT 0.048 81.792 103.312 81.888 ;
      RECT 0.048 82.560 103.312 82.656 ;
      RECT 0.048 83.328 103.312 83.424 ;
      RECT 0.048 84.096 103.312 84.192 ;
      RECT 0.048 84.864 103.312 84.960 ;
      RECT 0.048 85.632 103.312 85.728 ;
      RECT 0.048 86.400 103.312 86.496 ;
      RECT 0.048 87.168 103.312 87.264 ;
      RECT 0.048 87.936 103.312 88.032 ;
      RECT 0.048 88.704 103.312 88.800 ;
      RECT 0.048 89.472 103.312 89.568 ;
      RECT 0.048 90.240 103.312 90.336 ;
      RECT 0.048 91.008 103.312 91.104 ;
      RECT 0.048 91.776 103.312 91.872 ;
      RECT 0.048 92.544 103.312 92.640 ;
      RECT 0.048 93.312 103.312 93.408 ;
      RECT 0.048 94.080 103.312 94.176 ;
      RECT 0.048 94.848 103.312 94.944 ;
      RECT 0.048 95.616 103.312 95.712 ;
      RECT 0.048 96.384 103.312 96.480 ;
      RECT 0.048 97.152 103.312 97.248 ;
      RECT 0.048 97.920 103.312 98.016 ;
      RECT 0.048 98.688 103.312 98.784 ;
      RECT 0.048 99.456 103.312 99.552 ;
      RECT 0.048 100.224 103.312 100.320 ;
      RECT 0.048 100.992 103.312 101.088 ;
      RECT 0.048 101.760 103.312 101.856 ;
      RECT 0.048 102.528 103.312 102.624 ;
      RECT 0.048 103.296 103.312 103.392 ;
      RECT 0.048 104.064 103.312 104.160 ;
      RECT 0.048 104.832 103.312 104.928 ;
      RECT 0.048 105.600 103.312 105.696 ;
      RECT 0.048 106.368 103.312 106.464 ;
      RECT 0.048 107.136 103.312 107.232 ;
      RECT 0.048 107.904 103.312 108.000 ;
      RECT 0.048 108.672 103.312 108.768 ;
      RECT 0.048 109.440 103.312 109.536 ;
      RECT 0.048 110.208 103.312 110.304 ;
      RECT 0.048 110.976 103.312 111.072 ;
      RECT 0.048 111.744 103.312 111.840 ;
      RECT 0.048 112.512 103.312 112.608 ;
      RECT 0.048 113.280 103.312 113.376 ;
      RECT 0.048 114.048 103.312 114.144 ;
      RECT 0.048 114.816 103.312 114.912 ;
      RECT 0.048 115.584 103.312 115.680 ;
      RECT 0.048 116.352 103.312 116.448 ;
      RECT 0.048 117.120 103.312 117.216 ;
      RECT 0.048 117.888 103.312 117.984 ;
      RECT 0.048 118.656 103.312 118.752 ;
      RECT 0.048 119.424 103.312 119.520 ;
      RECT 0.048 120.192 103.312 120.288 ;
      RECT 0.048 120.960 103.312 121.056 ;
      RECT 0.048 121.728 103.312 121.824 ;
      RECT 0.048 122.496 103.312 122.592 ;
      RECT 0.048 123.264 103.312 123.360 ;
      RECT 0.048 124.032 103.312 124.128 ;
      RECT 0.048 124.800 103.312 124.896 ;
      RECT 0.048 125.568 103.312 125.664 ;
      RECT 0.048 126.336 103.312 126.432 ;
      RECT 0.048 127.104 103.312 127.200 ;
      RECT 0.048 127.872 103.312 127.968 ;
      RECT 0.048 128.640 103.312 128.736 ;
      RECT 0.048 129.408 103.312 129.504 ;
      RECT 0.048 130.176 103.312 130.272 ;
      RECT 0.048 130.944 103.312 131.040 ;
      RECT 0.048 131.712 103.312 131.808 ;
      RECT 0.048 132.480 103.312 132.576 ;
      RECT 0.048 133.248 103.312 133.344 ;
      RECT 0.048 134.016 103.312 134.112 ;
      RECT 0.048 134.784 103.312 134.880 ;
      RECT 0.048 135.552 103.312 135.648 ;
      RECT 0.048 136.320 103.312 136.416 ;
      RECT 0.048 137.088 103.312 137.184 ;
      RECT 0.048 137.856 103.312 137.952 ;
      RECT 0.048 138.624 103.312 138.720 ;
      RECT 0.048 139.392 103.312 139.488 ;
      RECT 0.048 140.160 103.312 140.256 ;
      RECT 0.048 140.928 103.312 141.024 ;
      RECT 0.048 141.696 103.312 141.792 ;
      RECT 0.048 142.464 103.312 142.560 ;
      RECT 0.048 143.232 103.312 143.328 ;
      RECT 0.048 144.000 103.312 144.096 ;
      RECT 0.048 144.768 103.312 144.864 ;
      RECT 0.048 145.536 103.312 145.632 ;
      RECT 0.048 146.304 103.312 146.400 ;
      RECT 0.048 147.072 103.312 147.168 ;
      RECT 0.048 147.840 103.312 147.936 ;
      RECT 0.048 148.608 103.312 148.704 ;
      RECT 0.048 149.376 103.312 149.472 ;
      RECT 0.048 150.144 103.312 150.240 ;
      RECT 0.048 150.912 103.312 151.008 ;
      RECT 0.048 151.680 103.312 151.776 ;
      RECT 0.048 152.448 103.312 152.544 ;
      RECT 0.048 153.216 103.312 153.312 ;
      RECT 0.048 153.984 103.312 154.080 ;
      RECT 0.048 154.752 103.312 154.848 ;
      RECT 0.048 155.520 103.312 155.616 ;
      RECT 0.048 156.288 103.312 156.384 ;
      RECT 0.048 157.056 103.312 157.152 ;
      RECT 0.048 157.824 103.312 157.920 ;
      RECT 0.048 158.592 103.312 158.688 ;
      RECT 0.048 159.360 103.312 159.456 ;
      RECT 0.048 160.128 103.312 160.224 ;
      RECT 0.048 160.896 103.312 160.992 ;
      RECT 0.048 161.664 103.312 161.760 ;
      RECT 0.048 162.432 103.312 162.528 ;
      RECT 0.048 163.200 103.312 163.296 ;
      RECT 0.048 163.968 103.312 164.064 ;
      RECT 0.048 164.736 103.312 164.832 ;
      RECT 0.048 165.504 103.312 165.600 ;
      RECT 0.048 166.272 103.312 166.368 ;
      RECT 0.048 167.040 103.312 167.136 ;
      RECT 0.048 167.808 103.312 167.904 ;
      RECT 0.048 168.576 103.312 168.672 ;
      RECT 0.048 169.344 103.312 169.440 ;
      RECT 0.048 170.112 103.312 170.208 ;
      RECT 0.048 170.880 103.312 170.976 ;
      RECT 0.048 171.648 103.312 171.744 ;
      RECT 0.048 172.416 103.312 172.512 ;
      RECT 0.048 173.184 103.312 173.280 ;
      RECT 0.048 173.952 103.312 174.048 ;
      RECT 0.048 174.720 103.312 174.816 ;
      RECT 0.048 175.488 103.312 175.584 ;
      RECT 0.048 176.256 103.312 176.352 ;
      RECT 0.048 177.024 103.312 177.120 ;
      RECT 0.048 177.792 103.312 177.888 ;
      RECT 0.048 178.560 103.312 178.656 ;
      RECT 0.048 179.328 103.312 179.424 ;
      RECT 0.048 180.096 103.312 180.192 ;
      RECT 0.048 180.864 103.312 180.960 ;
      RECT 0.048 181.632 103.312 181.728 ;
      RECT 0.048 182.400 103.312 182.496 ;
      RECT 0.048 183.168 103.312 183.264 ;
      RECT 0.048 183.936 103.312 184.032 ;
      RECT 0.048 184.704 103.312 184.800 ;
      RECT 0.048 185.472 103.312 185.568 ;
      RECT 0.048 186.240 103.312 186.336 ;
      RECT 0.048 187.008 103.312 187.104 ;
      RECT 0.048 187.776 103.312 187.872 ;
      RECT 0.048 188.544 103.312 188.640 ;
      RECT 0.048 189.312 103.312 189.408 ;
      RECT 0.048 190.080 103.312 190.176 ;
      RECT 0.048 190.848 103.312 190.944 ;
      RECT 0.048 191.616 103.312 191.712 ;
      RECT 0.048 192.384 103.312 192.480 ;
      RECT 0.048 193.152 103.312 193.248 ;
      RECT 0.048 193.920 103.312 194.016 ;
      RECT 0.048 194.688 103.312 194.784 ;
      RECT 0.048 195.456 103.312 195.552 ;
      RECT 0.048 196.224 103.312 196.320 ;
      RECT 0.048 196.992 103.312 197.088 ;
      RECT 0.048 197.760 103.312 197.856 ;
      RECT 0.048 198.528 103.312 198.624 ;
      RECT 0.048 199.296 103.312 199.392 ;
      RECT 0.048 200.064 103.312 200.160 ;
      RECT 0.048 200.832 103.312 200.928 ;
      RECT 0.048 201.600 103.312 201.696 ;
      RECT 0.048 202.368 103.312 202.464 ;
      RECT 0.048 203.136 103.312 203.232 ;
      RECT 0.048 203.904 103.312 204.000 ;
      RECT 0.048 204.672 103.312 204.768 ;
      RECT 0.048 205.440 103.312 205.536 ;
      RECT 0.048 206.208 103.312 206.304 ;
      RECT 0.048 206.976 103.312 207.072 ;
      RECT 0.048 207.744 103.312 207.840 ;
      RECT 0.048 208.512 103.312 208.608 ;
      RECT 0.048 209.280 103.312 209.376 ;
      RECT 0.048 210.048 103.312 210.144 ;
      RECT 0.048 210.816 103.312 210.912 ;
      RECT 0.048 211.584 103.312 211.680 ;
      RECT 0.048 212.352 103.312 212.448 ;
      RECT 0.048 213.120 103.312 213.216 ;
      RECT 0.048 213.888 103.312 213.984 ;
      RECT 0.048 214.656 103.312 214.752 ;
      RECT 0.048 215.424 103.312 215.520 ;
      RECT 0.048 216.192 103.312 216.288 ;
      RECT 0.048 216.960 103.312 217.056 ;
      RECT 0.048 217.728 103.312 217.824 ;
      RECT 0.048 218.496 103.312 218.592 ;
      RECT 0.048 219.264 103.312 219.360 ;
      RECT 0.048 220.032 103.312 220.128 ;
      RECT 0.048 220.800 103.312 220.896 ;
      RECT 0.048 221.568 103.312 221.664 ;
      RECT 0.048 222.336 103.312 222.432 ;
      RECT 0.048 223.104 103.312 223.200 ;
      RECT 0.048 223.872 103.312 223.968 ;
      RECT 0.048 224.640 103.312 224.736 ;
      RECT 0.048 225.408 103.312 225.504 ;
      RECT 0.048 226.176 103.312 226.272 ;
      RECT 0.048 226.944 103.312 227.040 ;
      RECT 0.048 227.712 103.312 227.808 ;
      RECT 0.048 228.480 103.312 228.576 ;
      RECT 0.048 229.248 103.312 229.344 ;
      RECT 0.048 230.016 103.312 230.112 ;
      RECT 0.048 230.784 103.312 230.880 ;
      RECT 0.048 231.552 103.312 231.648 ;
      RECT 0.048 232.320 103.312 232.416 ;
      RECT 0.048 233.088 103.312 233.184 ;
      RECT 0.048 233.856 103.312 233.952 ;
      RECT 0.048 234.624 103.312 234.720 ;
      RECT 0.048 235.392 103.312 235.488 ;
      RECT 0.048 236.160 103.312 236.256 ;
      RECT 0.048 236.928 103.312 237.024 ;
      RECT 0.048 237.696 103.312 237.792 ;
      RECT 0.048 238.464 103.312 238.560 ;
      RECT 0.048 239.232 103.312 239.328 ;
      RECT 0.048 240.000 103.312 240.096 ;
      RECT 0.048 240.768 103.312 240.864 ;
      RECT 0.048 241.536 103.312 241.632 ;
      RECT 0.048 242.304 103.312 242.400 ;
      RECT 0.048 243.072 103.312 243.168 ;
      RECT 0.048 243.840 103.312 243.936 ;
      RECT 0.048 244.608 103.312 244.704 ;
      RECT 0.048 245.376 103.312 245.472 ;
      RECT 0.048 246.144 103.312 246.240 ;
      RECT 0.048 246.912 103.312 247.008 ;
      RECT 0.048 247.680 103.312 247.776 ;
      RECT 0.048 248.448 103.312 248.544 ;
      RECT 0.048 249.216 103.312 249.312 ;
      RECT 0.048 249.984 103.312 250.080 ;
      RECT 0.048 250.752 103.312 250.848 ;
      RECT 0.048 251.520 103.312 251.616 ;
      RECT 0.048 252.288 103.312 252.384 ;
      RECT 0.048 253.056 103.312 253.152 ;
      RECT 0.048 253.824 103.312 253.920 ;
      RECT 0.048 254.592 103.312 254.688 ;
      RECT 0.048 255.360 103.312 255.456 ;
      RECT 0.048 256.128 103.312 256.224 ;
      RECT 0.048 256.896 103.312 256.992 ;
      RECT 0.048 257.664 103.312 257.760 ;
      RECT 0.048 258.432 103.312 258.528 ;
      RECT 0.048 259.200 103.312 259.296 ;
      RECT 0.048 259.968 103.312 260.064 ;
      RECT 0.048 260.736 103.312 260.832 ;
      RECT 0.048 261.504 103.312 261.600 ;
      RECT 0.048 262.272 103.312 262.368 ;
      RECT 0.048 263.040 103.312 263.136 ;
      RECT 0.048 263.808 103.312 263.904 ;
      RECT 0.048 264.576 103.312 264.672 ;
      RECT 0.048 265.344 103.312 265.440 ;
      RECT 0.048 266.112 103.312 266.208 ;
      RECT 0.048 266.880 103.312 266.976 ;
      RECT 0.048 267.648 103.312 267.744 ;
      RECT 0.048 268.416 103.312 268.512 ;
      RECT 0.048 269.184 103.312 269.280 ;
      RECT 0.048 269.952 103.312 270.048 ;
      RECT 0.048 270.720 103.312 270.816 ;
      RECT 0.048 271.488 103.312 271.584 ;
      RECT 0.048 272.256 103.312 272.352 ;
      RECT 0.048 273.024 103.312 273.120 ;
      RECT 0.048 273.792 103.312 273.888 ;
      RECT 0.048 274.560 103.312 274.656 ;
      RECT 0.048 275.328 103.312 275.424 ;
      RECT 0.048 276.096 103.312 276.192 ;
      RECT 0.048 276.864 103.312 276.960 ;
      RECT 0.048 277.632 103.312 277.728 ;
      RECT 0.048 278.400 103.312 278.496 ;
      RECT 0.048 279.168 103.312 279.264 ;
      RECT 0.048 279.936 103.312 280.032 ;
      RECT 0.048 280.704 103.312 280.800 ;
      RECT 0.048 281.472 103.312 281.568 ;
      RECT 0.048 282.240 103.312 282.336 ;
      RECT 0.048 283.008 103.312 283.104 ;
      RECT 0.048 283.776 103.312 283.872 ;
      RECT 0.048 284.544 103.312 284.640 ;
      RECT 0.048 285.312 103.312 285.408 ;
      RECT 0.048 286.080 103.312 286.176 ;
      RECT 0.048 286.848 103.312 286.944 ;
      RECT 0.048 287.616 103.312 287.712 ;
      RECT 0.048 288.384 103.312 288.480 ;
      RECT 0.048 289.152 103.312 289.248 ;
      RECT 0.048 289.920 103.312 290.016 ;
      RECT 0.048 290.688 103.312 290.784 ;
      RECT 0.048 291.456 103.312 291.552 ;
      RECT 0.048 292.224 103.312 292.320 ;
      RECT 0.048 292.992 103.312 293.088 ;
      RECT 0.048 293.760 103.312 293.856 ;
      RECT 0.048 294.528 103.312 294.624 ;
      RECT 0.048 295.296 103.312 295.392 ;
      RECT 0.048 296.064 103.312 296.160 ;
      RECT 0.048 296.832 103.312 296.928 ;
      RECT 0.048 297.600 103.312 297.696 ;
      RECT 0.048 298.368 103.312 298.464 ;
      RECT 0.048 299.136 103.312 299.232 ;
      RECT 0.048 299.904 103.312 300.000 ;
      RECT 0.048 300.672 103.312 300.768 ;
      RECT 0.048 301.440 103.312 301.536 ;
      RECT 0.048 302.208 103.312 302.304 ;
      RECT 0.048 302.976 103.312 303.072 ;
      RECT 0.048 303.744 103.312 303.840 ;
      RECT 0.048 304.512 103.312 304.608 ;
      RECT 0.048 305.280 103.312 305.376 ;
      RECT 0.048 306.048 103.312 306.144 ;
      RECT 0.048 306.816 103.312 306.912 ;
      RECT 0.048 307.584 103.312 307.680 ;
      RECT 0.048 308.352 103.312 308.448 ;
      RECT 0.048 309.120 103.312 309.216 ;
      RECT 0.048 309.888 103.312 309.984 ;
      RECT 0.048 310.656 103.312 310.752 ;
      RECT 0.048 311.424 103.312 311.520 ;
      RECT 0.048 312.192 103.312 312.288 ;
      RECT 0.048 312.960 103.312 313.056 ;
      RECT 0.048 313.728 103.312 313.824 ;
      RECT 0.048 314.496 103.312 314.592 ;
      RECT 0.048 315.264 103.312 315.360 ;
      RECT 0.048 316.032 103.312 316.128 ;
      RECT 0.048 316.800 103.312 316.896 ;
      RECT 0.048 317.568 103.312 317.664 ;
      RECT 0.048 318.336 103.312 318.432 ;
      RECT 0.048 319.104 103.312 319.200 ;
      RECT 0.048 319.872 103.312 319.968 ;
      RECT 0.048 320.640 103.312 320.736 ;
      RECT 0.048 321.408 103.312 321.504 ;
      RECT 0.048 322.176 103.312 322.272 ;
      RECT 0.048 322.944 103.312 323.040 ;
      RECT 0.048 323.712 103.312 323.808 ;
      RECT 0.048 324.480 103.312 324.576 ;
      RECT 0.048 325.248 103.312 325.344 ;
      RECT 0.048 326.016 103.312 326.112 ;
      RECT 0.048 326.784 103.312 326.880 ;
      RECT 0.048 327.552 103.312 327.648 ;
      RECT 0.048 328.320 103.312 328.416 ;
      RECT 0.048 329.088 103.312 329.184 ;
      RECT 0.048 329.856 103.312 329.952 ;
      RECT 0.048 330.624 103.312 330.720 ;
      RECT 0.048 331.392 103.312 331.488 ;
      RECT 0.048 332.160 103.312 332.256 ;
      RECT 0.048 332.928 103.312 333.024 ;
      RECT 0.048 333.696 103.312 333.792 ;
      RECT 0.048 334.464 103.312 334.560 ;
      RECT 0.048 335.232 103.312 335.328 ;
      RECT 0.048 336.000 103.312 336.096 ;
      RECT 0.048 336.768 103.312 336.864 ;
      RECT 0.048 337.536 103.312 337.632 ;
      RECT 0.048 338.304 103.312 338.400 ;
      RECT 0.048 339.072 103.312 339.168 ;
      RECT 0.048 339.840 103.312 339.936 ;
      RECT 0.048 340.608 103.312 340.704 ;
      RECT 0.048 341.376 103.312 341.472 ;
      RECT 0.048 342.144 103.312 342.240 ;
      RECT 0.048 342.912 103.312 343.008 ;
      RECT 0.048 343.680 103.312 343.776 ;
      RECT 0.048 344.448 103.312 344.544 ;
      RECT 0.048 345.216 103.312 345.312 ;
      RECT 0.048 345.984 103.312 346.080 ;
      RECT 0.048 346.752 103.312 346.848 ;
      RECT 0.048 347.520 103.312 347.616 ;
      RECT 0.048 348.288 103.312 348.384 ;
      RECT 0.048 349.056 103.312 349.152 ;
      RECT 0.048 349.824 103.312 349.920 ;
      RECT 0.048 350.592 103.312 350.688 ;
      RECT 0.048 351.360 103.312 351.456 ;
      RECT 0.048 352.128 103.312 352.224 ;
      RECT 0.048 352.896 103.312 352.992 ;
      RECT 0.048 353.664 103.312 353.760 ;
      RECT 0.048 354.432 103.312 354.528 ;
      RECT 0.048 355.200 103.312 355.296 ;
      RECT 0.048 355.968 103.312 356.064 ;
      RECT 0.048 356.736 103.312 356.832 ;
      RECT 0.048 357.504 103.312 357.600 ;
      RECT 0.048 358.272 103.312 358.368 ;
      RECT 0.048 359.040 103.312 359.136 ;
      RECT 0.048 359.808 103.312 359.904 ;
      RECT 0.048 360.576 103.312 360.672 ;
      RECT 0.048 361.344 103.312 361.440 ;
      RECT 0.048 362.112 103.312 362.208 ;
      RECT 0.048 362.880 103.312 362.976 ;
      RECT 0.048 363.648 103.312 363.744 ;
      RECT 0.048 364.416 103.312 364.512 ;
      RECT 0.048 365.184 103.312 365.280 ;
    END
  END VDD
  OBS
    LAYER M1 ;
    RECT 0 0 103.360 365.400 ;
    LAYER M2 ;
    RECT 0 0 103.360 365.400 ;
    LAYER M3 ;
    RECT 0 0 103.360 365.400 ;
    LAYER M4 ;
    RECT 0 0 103.360 365.400 ;
  END
END fakeram7_tdp_8192x64

END LIBRARY
